VERSION 5.8 ;
BUSBITCHARS "[]" ;
DIVIDERCHAR "/" ;
UNITS
    DATABASE MICRONS 1000 ;
END UNITS

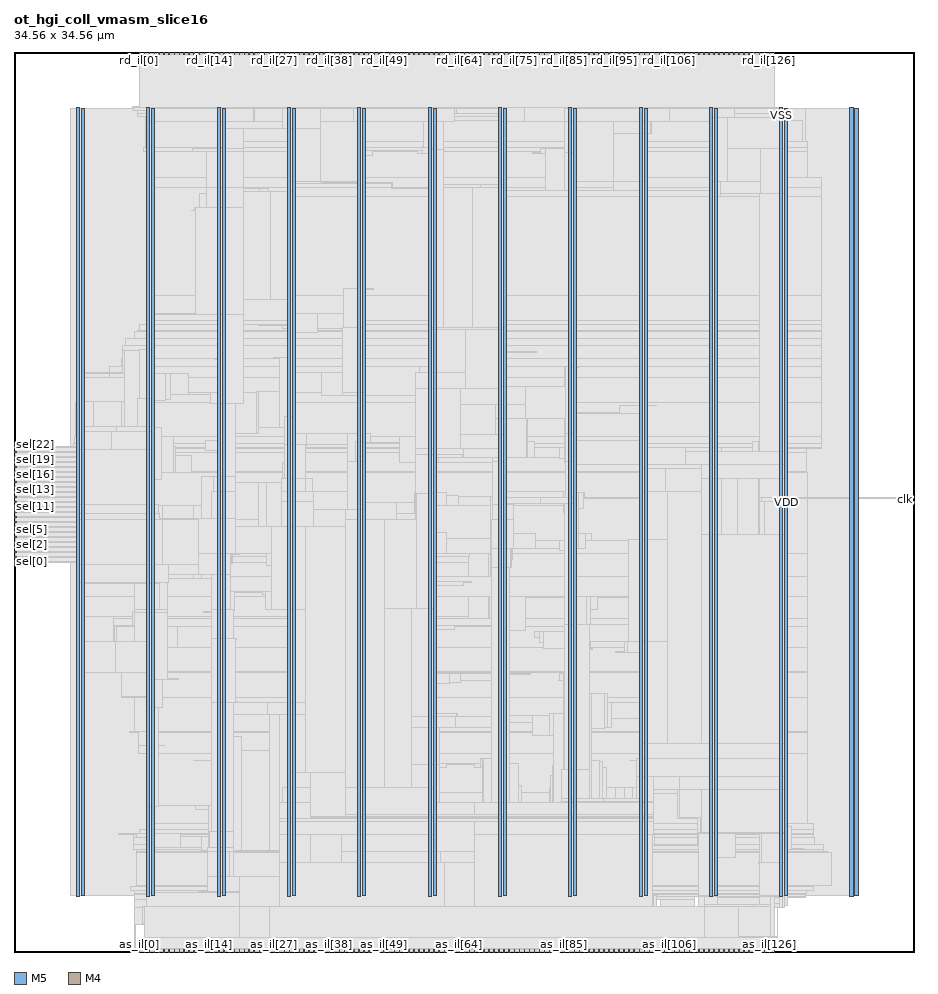
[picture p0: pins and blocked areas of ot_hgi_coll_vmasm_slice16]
MACRO ot_hgi_coll_vmasm_slice16
  FOREIGN ot_hgi_coll_vmasm_slice16 0 0 ;
  CLASS BLOCK ;
  SIZE 34.56 BY 34.56 ;
  PIN as_il[0]
    DIRECTION OUTPUT ;
    USE SIGNAL ;
    PORT
      LAYER M5 ;
        RECT  4.8 0 4.824 0.084 ;
    END
  END as_il[0]
  PIN as_il[100]
    DIRECTION OUTPUT ;
    USE SIGNAL ;
    PORT
      LAYER M5 ;
        RECT  24 0 24.024 0.084 ;
    END
  END as_il[100]
  PIN as_il[101]
    DIRECTION OUTPUT ;
    USE SIGNAL ;
    PORT
      LAYER M5 ;
        RECT  24.192 0 24.216 0.084 ;
    END
  END as_il[101]
  PIN as_il[102]
    DIRECTION OUTPUT ;
    USE SIGNAL ;
    PORT
      LAYER M5 ;
        RECT  24.384 0 24.408 0.084 ;
    END
  END as_il[102]
  PIN as_il[103]
    DIRECTION OUTPUT ;
    USE SIGNAL ;
    PORT
      LAYER M5 ;
        RECT  24.576 0 24.6 0.084 ;
    END
  END as_il[103]
  PIN as_il[104]
    DIRECTION OUTPUT ;
    USE SIGNAL ;
    PORT
      LAYER M5 ;
        RECT  24.768 0 24.792 0.084 ;
    END
  END as_il[104]
  PIN as_il[105]
    DIRECTION OUTPUT ;
    USE SIGNAL ;
    PORT
      LAYER M5 ;
        RECT  24.96 0 24.984 0.084 ;
    END
  END as_il[105]
  PIN as_il[106]
    DIRECTION OUTPUT ;
    USE SIGNAL ;
    PORT
      LAYER M5 ;
        RECT  25.152 0 25.176 0.084 ;
    END
  END as_il[106]
  PIN as_il[107]
    DIRECTION OUTPUT ;
    USE SIGNAL ;
    PORT
      LAYER M5 ;
        RECT  25.344 0 25.368 0.084 ;
    END
  END as_il[107]
  PIN as_il[108]
    DIRECTION OUTPUT ;
    USE SIGNAL ;
    PORT
      LAYER M5 ;
        RECT  25.536 0 25.56 0.084 ;
    END
  END as_il[108]
  PIN as_il[109]
    DIRECTION OUTPUT ;
    USE SIGNAL ;
    PORT
      LAYER M5 ;
        RECT  25.728 0 25.752 0.084 ;
    END
  END as_il[109]
  PIN as_il[10]
    DIRECTION OUTPUT ;
    USE SIGNAL ;
    PORT
      LAYER M5 ;
        RECT  6.72 0 6.744 0.084 ;
    END
  END as_il[10]
  PIN as_il[110]
    DIRECTION OUTPUT ;
    USE SIGNAL ;
    PORT
      LAYER M5 ;
        RECT  25.92 0 25.944 0.084 ;
    END
  END as_il[110]
  PIN as_il[111]
    DIRECTION OUTPUT ;
    USE SIGNAL ;
    PORT
      LAYER M5 ;
        RECT  26.112 0 26.136 0.084 ;
    END
  END as_il[111]
  PIN as_il[112]
    DIRECTION OUTPUT ;
    USE SIGNAL ;
    PORT
      LAYER M5 ;
        RECT  26.304 0 26.328 0.084 ;
    END
  END as_il[112]
  PIN as_il[113]
    DIRECTION OUTPUT ;
    USE SIGNAL ;
    PORT
      LAYER M5 ;
        RECT  26.496 0 26.52 0.084 ;
    END
  END as_il[113]
  PIN as_il[114]
    DIRECTION OUTPUT ;
    USE SIGNAL ;
    PORT
      LAYER M5 ;
        RECT  26.688 0 26.712 0.084 ;
    END
  END as_il[114]
  PIN as_il[115]
    DIRECTION OUTPUT ;
    USE SIGNAL ;
    PORT
      LAYER M5 ;
        RECT  26.88 0 26.904 0.084 ;
    END
  END as_il[115]
  PIN as_il[116]
    DIRECTION OUTPUT ;
    USE SIGNAL ;
    PORT
      LAYER M5 ;
        RECT  27.072 0 27.096 0.084 ;
    END
  END as_il[116]
  PIN as_il[117]
    DIRECTION OUTPUT ;
    USE SIGNAL ;
    PORT
      LAYER M5 ;
        RECT  27.264 0 27.288 0.084 ;
    END
  END as_il[117]
  PIN as_il[118]
    DIRECTION OUTPUT ;
    USE SIGNAL ;
    PORT
      LAYER M5 ;
        RECT  27.456 0 27.48 0.084 ;
    END
  END as_il[118]
  PIN as_il[119]
    DIRECTION OUTPUT ;
    USE SIGNAL ;
    PORT
      LAYER M5 ;
        RECT  27.648 0 27.672 0.084 ;
    END
  END as_il[119]
  PIN as_il[11]
    DIRECTION OUTPUT ;
    USE SIGNAL ;
    PORT
      LAYER M5 ;
        RECT  6.912 0 6.936 0.084 ;
    END
  END as_il[11]
  PIN as_il[120]
    DIRECTION OUTPUT ;
    USE SIGNAL ;
    PORT
      LAYER M5 ;
        RECT  27.84 0 27.864 0.084 ;
    END
  END as_il[120]
  PIN as_il[121]
    DIRECTION OUTPUT ;
    USE SIGNAL ;
    PORT
      LAYER M5 ;
        RECT  28.032 0 28.056 0.084 ;
    END
  END as_il[121]
  PIN as_il[122]
    DIRECTION OUTPUT ;
    USE SIGNAL ;
    PORT
      LAYER M5 ;
        RECT  28.224 0 28.248 0.084 ;
    END
  END as_il[122]
  PIN as_il[123]
    DIRECTION OUTPUT ;
    USE SIGNAL ;
    PORT
      LAYER M5 ;
        RECT  28.416 0 28.44 0.084 ;
    END
  END as_il[123]
  PIN as_il[124]
    DIRECTION OUTPUT ;
    USE SIGNAL ;
    PORT
      LAYER M5 ;
        RECT  28.608 0 28.632 0.084 ;
    END
  END as_il[124]
  PIN as_il[125]
    DIRECTION OUTPUT ;
    USE SIGNAL ;
    PORT
      LAYER M5 ;
        RECT  28.8 0 28.824 0.084 ;
    END
  END as_il[125]
  PIN as_il[126]
    DIRECTION OUTPUT ;
    USE SIGNAL ;
    PORT
      LAYER M5 ;
        RECT  28.992 0 29.016 0.084 ;
    END
  END as_il[126]
  PIN as_il[127]
    DIRECTION OUTPUT ;
    USE SIGNAL ;
    PORT
      LAYER M5 ;
        RECT  29.184 0 29.208 0.084 ;
    END
  END as_il[127]
  PIN as_il[12]
    DIRECTION OUTPUT ;
    USE SIGNAL ;
    PORT
      LAYER M5 ;
        RECT  7.104 0 7.128 0.084 ;
    END
  END as_il[12]
  PIN as_il[13]
    DIRECTION OUTPUT ;
    USE SIGNAL ;
    PORT
      LAYER M5 ;
        RECT  7.296 0 7.32 0.084 ;
    END
  END as_il[13]
  PIN as_il[14]
    DIRECTION OUTPUT ;
    USE SIGNAL ;
    PORT
      LAYER M5 ;
        RECT  7.488 0 7.512 0.084 ;
    END
  END as_il[14]
  PIN as_il[15]
    DIRECTION OUTPUT ;
    USE SIGNAL ;
    PORT
      LAYER M5 ;
        RECT  7.68 0 7.704 0.084 ;
    END
  END as_il[15]
  PIN as_il[16]
    DIRECTION OUTPUT ;
    USE SIGNAL ;
    PORT
      LAYER M5 ;
        RECT  7.872 0 7.896 0.084 ;
    END
  END as_il[16]
  PIN as_il[17]
    DIRECTION OUTPUT ;
    USE SIGNAL ;
    PORT
      LAYER M5 ;
        RECT  8.064 0 8.088 0.084 ;
    END
  END as_il[17]
  PIN as_il[18]
    DIRECTION OUTPUT ;
    USE SIGNAL ;
    PORT
      LAYER M5 ;
        RECT  8.256 0 8.28 0.084 ;
    END
  END as_il[18]
  PIN as_il[19]
    DIRECTION OUTPUT ;
    USE SIGNAL ;
    PORT
      LAYER M5 ;
        RECT  8.448 0 8.472 0.084 ;
    END
  END as_il[19]
  PIN as_il[1]
    DIRECTION OUTPUT ;
    USE SIGNAL ;
    PORT
      LAYER M5 ;
        RECT  4.992 0 5.016 0.084 ;
    END
  END as_il[1]
  PIN as_il[20]
    DIRECTION OUTPUT ;
    USE SIGNAL ;
    PORT
      LAYER M5 ;
        RECT  8.64 0 8.664 0.084 ;
    END
  END as_il[20]
  PIN as_il[21]
    DIRECTION OUTPUT ;
    USE SIGNAL ;
    PORT
      LAYER M5 ;
        RECT  8.832 0 8.856 0.084 ;
    END
  END as_il[21]
  PIN as_il[22]
    DIRECTION OUTPUT ;
    USE SIGNAL ;
    PORT
      LAYER M5 ;
        RECT  9.024 0 9.048 0.084 ;
    END
  END as_il[22]
  PIN as_il[23]
    DIRECTION OUTPUT ;
    USE SIGNAL ;
    PORT
      LAYER M5 ;
        RECT  9.216 0 9.24 0.084 ;
    END
  END as_il[23]
  PIN as_il[24]
    DIRECTION OUTPUT ;
    USE SIGNAL ;
    PORT
      LAYER M5 ;
        RECT  9.408 0 9.432 0.084 ;
    END
  END as_il[24]
  PIN as_il[25]
    DIRECTION OUTPUT ;
    USE SIGNAL ;
    PORT
      LAYER M5 ;
        RECT  9.6 0 9.624 0.084 ;
    END
  END as_il[25]
  PIN as_il[26]
    DIRECTION OUTPUT ;
    USE SIGNAL ;
    PORT
      LAYER M5 ;
        RECT  9.792 0 9.816 0.084 ;
    END
  END as_il[26]
  PIN as_il[27]
    DIRECTION OUTPUT ;
    USE SIGNAL ;
    PORT
      LAYER M5 ;
        RECT  9.984 0 10.008 0.084 ;
    END
  END as_il[27]
  PIN as_il[28]
    DIRECTION OUTPUT ;
    USE SIGNAL ;
    PORT
      LAYER M5 ;
        RECT  10.176 0 10.2 0.084 ;
    END
  END as_il[28]
  PIN as_il[29]
    DIRECTION OUTPUT ;
    USE SIGNAL ;
    PORT
      LAYER M5 ;
        RECT  10.368 0 10.392 0.084 ;
    END
  END as_il[29]
  PIN as_il[2]
    DIRECTION OUTPUT ;
    USE SIGNAL ;
    PORT
      LAYER M5 ;
        RECT  5.184 0 5.208 0.084 ;
    END
  END as_il[2]
  PIN as_il[30]
    DIRECTION OUTPUT ;
    USE SIGNAL ;
    PORT
      LAYER M5 ;
        RECT  10.56 0 10.584 0.084 ;
    END
  END as_il[30]
  PIN as_il[31]
    DIRECTION OUTPUT ;
    USE SIGNAL ;
    PORT
      LAYER M5 ;
        RECT  10.752 0 10.776 0.084 ;
    END
  END as_il[31]
  PIN as_il[32]
    DIRECTION OUTPUT ;
    USE SIGNAL ;
    PORT
      LAYER M5 ;
        RECT  10.944 0 10.968 0.084 ;
    END
  END as_il[32]
  PIN as_il[33]
    DIRECTION OUTPUT ;
    USE SIGNAL ;
    PORT
      LAYER M5 ;
        RECT  11.136 0 11.16 0.084 ;
    END
  END as_il[33]
  PIN as_il[34]
    DIRECTION OUTPUT ;
    USE SIGNAL ;
    PORT
      LAYER M5 ;
        RECT  11.328 0 11.352 0.084 ;
    END
  END as_il[34]
  PIN as_il[35]
    DIRECTION OUTPUT ;
    USE SIGNAL ;
    PORT
      LAYER M5 ;
        RECT  11.52 0 11.544 0.084 ;
    END
  END as_il[35]
  PIN as_il[36]
    DIRECTION OUTPUT ;
    USE SIGNAL ;
    PORT
      LAYER M5 ;
        RECT  11.712 0 11.736 0.084 ;
    END
  END as_il[36]
  PIN as_il[37]
    DIRECTION OUTPUT ;
    USE SIGNAL ;
    PORT
      LAYER M5 ;
        RECT  11.904 0 11.928 0.084 ;
    END
  END as_il[37]
  PIN as_il[38]
    DIRECTION OUTPUT ;
    USE SIGNAL ;
    PORT
      LAYER M5 ;
        RECT  12.096 0 12.12 0.084 ;
    END
  END as_il[38]
  PIN as_il[39]
    DIRECTION OUTPUT ;
    USE SIGNAL ;
    PORT
      LAYER M5 ;
        RECT  12.288 0 12.312 0.084 ;
    END
  END as_il[39]
  PIN as_il[3]
    DIRECTION OUTPUT ;
    USE SIGNAL ;
    PORT
      LAYER M5 ;
        RECT  5.376 0 5.4 0.084 ;
    END
  END as_il[3]
  PIN as_il[40]
    DIRECTION OUTPUT ;
    USE SIGNAL ;
    PORT
      LAYER M5 ;
        RECT  12.48 0 12.504 0.084 ;
    END
  END as_il[40]
  PIN as_il[41]
    DIRECTION OUTPUT ;
    USE SIGNAL ;
    PORT
      LAYER M5 ;
        RECT  12.672 0 12.696 0.084 ;
    END
  END as_il[41]
  PIN as_il[42]
    DIRECTION OUTPUT ;
    USE SIGNAL ;
    PORT
      LAYER M5 ;
        RECT  12.864 0 12.888 0.084 ;
    END
  END as_il[42]
  PIN as_il[43]
    DIRECTION OUTPUT ;
    USE SIGNAL ;
    PORT
      LAYER M5 ;
        RECT  13.056 0 13.08 0.084 ;
    END
  END as_il[43]
  PIN as_il[44]
    DIRECTION OUTPUT ;
    USE SIGNAL ;
    PORT
      LAYER M5 ;
        RECT  13.248 0 13.272 0.084 ;
    END
  END as_il[44]
  PIN as_il[45]
    DIRECTION OUTPUT ;
    USE SIGNAL ;
    PORT
      LAYER M5 ;
        RECT  13.44 0 13.464 0.084 ;
    END
  END as_il[45]
  PIN as_il[46]
    DIRECTION OUTPUT ;
    USE SIGNAL ;
    PORT
      LAYER M5 ;
        RECT  13.632 0 13.656 0.084 ;
    END
  END as_il[46]
  PIN as_il[47]
    DIRECTION OUTPUT ;
    USE SIGNAL ;
    PORT
      LAYER M5 ;
        RECT  13.824 0 13.848 0.084 ;
    END
  END as_il[47]
  PIN as_il[48]
    DIRECTION OUTPUT ;
    USE SIGNAL ;
    PORT
      LAYER M5 ;
        RECT  14.016 0 14.04 0.084 ;
    END
  END as_il[48]
  PIN as_il[49]
    DIRECTION OUTPUT ;
    USE SIGNAL ;
    PORT
      LAYER M5 ;
        RECT  14.208 0 14.232 0.084 ;
    END
  END as_il[49]
  PIN as_il[4]
    DIRECTION OUTPUT ;
    USE SIGNAL ;
    PORT
      LAYER M5 ;
        RECT  5.568 0 5.592 0.084 ;
    END
  END as_il[4]
  PIN as_il[50]
    DIRECTION OUTPUT ;
    USE SIGNAL ;
    PORT
      LAYER M5 ;
        RECT  14.4 0 14.424 0.084 ;
    END
  END as_il[50]
  PIN as_il[51]
    DIRECTION OUTPUT ;
    USE SIGNAL ;
    PORT
      LAYER M5 ;
        RECT  14.592 0 14.616 0.084 ;
    END
  END as_il[51]
  PIN as_il[52]
    DIRECTION OUTPUT ;
    USE SIGNAL ;
    PORT
      LAYER M5 ;
        RECT  14.784 0 14.808 0.084 ;
    END
  END as_il[52]
  PIN as_il[53]
    DIRECTION OUTPUT ;
    USE SIGNAL ;
    PORT
      LAYER M5 ;
        RECT  14.976 0 15 0.084 ;
    END
  END as_il[53]
  PIN as_il[54]
    DIRECTION OUTPUT ;
    USE SIGNAL ;
    PORT
      LAYER M5 ;
        RECT  15.168 0 15.192 0.084 ;
    END
  END as_il[54]
  PIN as_il[55]
    DIRECTION OUTPUT ;
    USE SIGNAL ;
    PORT
      LAYER M5 ;
        RECT  15.36 0 15.384 0.084 ;
    END
  END as_il[55]
  PIN as_il[56]
    DIRECTION OUTPUT ;
    USE SIGNAL ;
    PORT
      LAYER M5 ;
        RECT  15.552 0 15.576 0.084 ;
    END
  END as_il[56]
  PIN as_il[57]
    DIRECTION OUTPUT ;
    USE SIGNAL ;
    PORT
      LAYER M5 ;
        RECT  15.744 0 15.768 0.084 ;
    END
  END as_il[57]
  PIN as_il[58]
    DIRECTION OUTPUT ;
    USE SIGNAL ;
    PORT
      LAYER M5 ;
        RECT  15.936 0 15.96 0.084 ;
    END
  END as_il[58]
  PIN as_il[59]
    DIRECTION OUTPUT ;
    USE SIGNAL ;
    PORT
      LAYER M5 ;
        RECT  16.128 0 16.152 0.084 ;
    END
  END as_il[59]
  PIN as_il[5]
    DIRECTION OUTPUT ;
    USE SIGNAL ;
    PORT
      LAYER M5 ;
        RECT  5.76 0 5.784 0.084 ;
    END
  END as_il[5]
  PIN as_il[60]
    DIRECTION OUTPUT ;
    USE SIGNAL ;
    PORT
      LAYER M5 ;
        RECT  16.32 0 16.344 0.084 ;
    END
  END as_il[60]
  PIN as_il[61]
    DIRECTION OUTPUT ;
    USE SIGNAL ;
    PORT
      LAYER M5 ;
        RECT  16.512 0 16.536 0.084 ;
    END
  END as_il[61]
  PIN as_il[62]
    DIRECTION OUTPUT ;
    USE SIGNAL ;
    PORT
      LAYER M5 ;
        RECT  16.704 0 16.728 0.084 ;
    END
  END as_il[62]
  PIN as_il[63]
    DIRECTION OUTPUT ;
    USE SIGNAL ;
    PORT
      LAYER M5 ;
        RECT  16.896 0 16.92 0.084 ;
    END
  END as_il[63]
  PIN as_il[64]
    DIRECTION OUTPUT ;
    USE SIGNAL ;
    PORT
      LAYER M5 ;
        RECT  17.088 0 17.112 0.084 ;
    END
  END as_il[64]
  PIN as_il[65]
    DIRECTION OUTPUT ;
    USE SIGNAL ;
    PORT
      LAYER M5 ;
        RECT  17.28 0 17.304 0.084 ;
    END
  END as_il[65]
  PIN as_il[66]
    DIRECTION OUTPUT ;
    USE SIGNAL ;
    PORT
      LAYER M5 ;
        RECT  17.472 0 17.496 0.084 ;
    END
  END as_il[66]
  PIN as_il[67]
    DIRECTION OUTPUT ;
    USE SIGNAL ;
    PORT
      LAYER M5 ;
        RECT  17.664 0 17.688 0.084 ;
    END
  END as_il[67]
  PIN as_il[68]
    DIRECTION OUTPUT ;
    USE SIGNAL ;
    PORT
      LAYER M5 ;
        RECT  17.856 0 17.88 0.084 ;
    END
  END as_il[68]
  PIN as_il[69]
    DIRECTION OUTPUT ;
    USE SIGNAL ;
    PORT
      LAYER M5 ;
        RECT  18.048 0 18.072 0.084 ;
    END
  END as_il[69]
  PIN as_il[6]
    DIRECTION OUTPUT ;
    USE SIGNAL ;
    PORT
      LAYER M5 ;
        RECT  5.952 0 5.976 0.084 ;
    END
  END as_il[6]
  PIN as_il[70]
    DIRECTION OUTPUT ;
    USE SIGNAL ;
    PORT
      LAYER M5 ;
        RECT  18.24 0 18.264 0.084 ;
    END
  END as_il[70]
  PIN as_il[71]
    DIRECTION OUTPUT ;
    USE SIGNAL ;
    PORT
      LAYER M5 ;
        RECT  18.432 0 18.456 0.084 ;
    END
  END as_il[71]
  PIN as_il[72]
    DIRECTION OUTPUT ;
    USE SIGNAL ;
    PORT
      LAYER M5 ;
        RECT  18.624 0 18.648 0.084 ;
    END
  END as_il[72]
  PIN as_il[73]
    DIRECTION OUTPUT ;
    USE SIGNAL ;
    PORT
      LAYER M5 ;
        RECT  18.816 0 18.84 0.084 ;
    END
  END as_il[73]
  PIN as_il[74]
    DIRECTION OUTPUT ;
    USE SIGNAL ;
    PORT
      LAYER M5 ;
        RECT  19.008 0 19.032 0.084 ;
    END
  END as_il[74]
  PIN as_il[75]
    DIRECTION OUTPUT ;
    USE SIGNAL ;
    PORT
      LAYER M5 ;
        RECT  19.2 0 19.224 0.084 ;
    END
  END as_il[75]
  PIN as_il[76]
    DIRECTION OUTPUT ;
    USE SIGNAL ;
    PORT
      LAYER M5 ;
        RECT  19.392 0 19.416 0.084 ;
    END
  END as_il[76]
  PIN as_il[77]
    DIRECTION OUTPUT ;
    USE SIGNAL ;
    PORT
      LAYER M5 ;
        RECT  19.584 0 19.608 0.084 ;
    END
  END as_il[77]
  PIN as_il[78]
    DIRECTION OUTPUT ;
    USE SIGNAL ;
    PORT
      LAYER M5 ;
        RECT  19.776 0 19.8 0.084 ;
    END
  END as_il[78]
  PIN as_il[79]
    DIRECTION OUTPUT ;
    USE SIGNAL ;
    PORT
      LAYER M5 ;
        RECT  19.968 0 19.992 0.084 ;
    END
  END as_il[79]
  PIN as_il[7]
    DIRECTION OUTPUT ;
    USE SIGNAL ;
    PORT
      LAYER M5 ;
        RECT  6.144 0 6.168 0.084 ;
    END
  END as_il[7]
  PIN as_il[80]
    DIRECTION OUTPUT ;
    USE SIGNAL ;
    PORT
      LAYER M5 ;
        RECT  20.16 0 20.184 0.084 ;
    END
  END as_il[80]
  PIN as_il[81]
    DIRECTION OUTPUT ;
    USE SIGNAL ;
    PORT
      LAYER M5 ;
        RECT  20.352 0 20.376 0.084 ;
    END
  END as_il[81]
  PIN as_il[82]
    DIRECTION OUTPUT ;
    USE SIGNAL ;
    PORT
      LAYER M5 ;
        RECT  20.544 0 20.568 0.084 ;
    END
  END as_il[82]
  PIN as_il[83]
    DIRECTION OUTPUT ;
    USE SIGNAL ;
    PORT
      LAYER M5 ;
        RECT  20.736 0 20.76 0.084 ;
    END
  END as_il[83]
  PIN as_il[84]
    DIRECTION OUTPUT ;
    USE SIGNAL ;
    PORT
      LAYER M5 ;
        RECT  20.928 0 20.952 0.084 ;
    END
  END as_il[84]
  PIN as_il[85]
    DIRECTION OUTPUT ;
    USE SIGNAL ;
    PORT
      LAYER M5 ;
        RECT  21.12 0 21.144 0.084 ;
    END
  END as_il[85]
  PIN as_il[86]
    DIRECTION OUTPUT ;
    USE SIGNAL ;
    PORT
      LAYER M5 ;
        RECT  21.312 0 21.336 0.084 ;
    END
  END as_il[86]
  PIN as_il[87]
    DIRECTION OUTPUT ;
    USE SIGNAL ;
    PORT
      LAYER M5 ;
        RECT  21.504 0 21.528 0.084 ;
    END
  END as_il[87]
  PIN as_il[88]
    DIRECTION OUTPUT ;
    USE SIGNAL ;
    PORT
      LAYER M5 ;
        RECT  21.696 0 21.72 0.084 ;
    END
  END as_il[88]
  PIN as_il[89]
    DIRECTION OUTPUT ;
    USE SIGNAL ;
    PORT
      LAYER M5 ;
        RECT  21.888 0 21.912 0.084 ;
    END
  END as_il[89]
  PIN as_il[8]
    DIRECTION OUTPUT ;
    USE SIGNAL ;
    PORT
      LAYER M5 ;
        RECT  6.336 0 6.36 0.084 ;
    END
  END as_il[8]
  PIN as_il[90]
    DIRECTION OUTPUT ;
    USE SIGNAL ;
    PORT
      LAYER M5 ;
        RECT  22.08 0 22.104 0.084 ;
    END
  END as_il[90]
  PIN as_il[91]
    DIRECTION OUTPUT ;
    USE SIGNAL ;
    PORT
      LAYER M5 ;
        RECT  22.272 0 22.296 0.084 ;
    END
  END as_il[91]
  PIN as_il[92]
    DIRECTION OUTPUT ;
    USE SIGNAL ;
    PORT
      LAYER M5 ;
        RECT  22.464 0 22.488 0.084 ;
    END
  END as_il[92]
  PIN as_il[93]
    DIRECTION OUTPUT ;
    USE SIGNAL ;
    PORT
      LAYER M5 ;
        RECT  22.656 0 22.68 0.084 ;
    END
  END as_il[93]
  PIN as_il[94]
    DIRECTION OUTPUT ;
    USE SIGNAL ;
    PORT
      LAYER M5 ;
        RECT  22.848 0 22.872 0.084 ;
    END
  END as_il[94]
  PIN as_il[95]
    DIRECTION OUTPUT ;
    USE SIGNAL ;
    PORT
      LAYER M5 ;
        RECT  23.04 0 23.064 0.084 ;
    END
  END as_il[95]
  PIN as_il[96]
    DIRECTION OUTPUT ;
    USE SIGNAL ;
    PORT
      LAYER M5 ;
        RECT  23.232 0 23.256 0.084 ;
    END
  END as_il[96]
  PIN as_il[97]
    DIRECTION OUTPUT ;
    USE SIGNAL ;
    PORT
      LAYER M5 ;
        RECT  23.424 0 23.448 0.084 ;
    END
  END as_il[97]
  PIN as_il[98]
    DIRECTION OUTPUT ;
    USE SIGNAL ;
    PORT
      LAYER M5 ;
        RECT  23.616 0 23.64 0.084 ;
    END
  END as_il[98]
  PIN as_il[99]
    DIRECTION OUTPUT ;
    USE SIGNAL ;
    PORT
      LAYER M5 ;
        RECT  23.808 0 23.832 0.084 ;
    END
  END as_il[99]
  PIN as_il[9]
    DIRECTION OUTPUT ;
    USE SIGNAL ;
    PORT
      LAYER M5 ;
        RECT  6.528 0 6.552 0.084 ;
    END
  END as_il[9]
  PIN clk
    DIRECTION INPUT ;
    USE SIGNAL ;
    PORT
      LAYER M4 ;
        RECT  34.476 17.28 34.56 17.304 ;
    END
    PORT
      LAYER M4 ;
        RECT  34.441 17.28 34.481 17.448 ;
    END
    PORT
      LAYER M4 ;
        RECT  34.481 17.28 34.524 17.304 ;
    END
  END clk
  PIN rd_il[0]
    DIRECTION INPUT ;
    USE SIGNAL ;
    PORT
      LAYER M5 ;
        RECT  4.8 34.476 4.824 34.56 ;
    END
  END rd_il[0]
  PIN rd_il[100]
    DIRECTION INPUT ;
    USE SIGNAL ;
    PORT
      LAYER M5 ;
        RECT  24 34.476 24.024 34.56 ;
    END
  END rd_il[100]
  PIN rd_il[101]
    DIRECTION INPUT ;
    USE SIGNAL ;
    PORT
      LAYER M5 ;
        RECT  24.192 34.476 24.216 34.56 ;
    END
  END rd_il[101]
  PIN rd_il[102]
    DIRECTION INPUT ;
    USE SIGNAL ;
    PORT
      LAYER M5 ;
        RECT  24.384 34.476 24.408 34.56 ;
    END
  END rd_il[102]
  PIN rd_il[103]
    DIRECTION INPUT ;
    USE SIGNAL ;
    PORT
      LAYER M5 ;
        RECT  24.576 34.476 24.6 34.56 ;
    END
  END rd_il[103]
  PIN rd_il[104]
    DIRECTION INPUT ;
    USE SIGNAL ;
    PORT
      LAYER M5 ;
        RECT  24.768 34.476 24.792 34.56 ;
    END
  END rd_il[104]
  PIN rd_il[105]
    DIRECTION INPUT ;
    USE SIGNAL ;
    PORT
      LAYER M5 ;
        RECT  24.96 34.476 24.984 34.56 ;
    END
  END rd_il[105]
  PIN rd_il[106]
    DIRECTION INPUT ;
    USE SIGNAL ;
    PORT
      LAYER M5 ;
        RECT  25.152 34.476 25.176 34.56 ;
    END
  END rd_il[106]
  PIN rd_il[107]
    DIRECTION INPUT ;
    USE SIGNAL ;
    PORT
      LAYER M5 ;
        RECT  25.344 34.476 25.368 34.56 ;
    END
  END rd_il[107]
  PIN rd_il[108]
    DIRECTION INPUT ;
    USE SIGNAL ;
    PORT
      LAYER M5 ;
        RECT  25.536 34.476 25.56 34.56 ;
    END
  END rd_il[108]
  PIN rd_il[109]
    DIRECTION INPUT ;
    USE SIGNAL ;
    PORT
      LAYER M5 ;
        RECT  25.728 34.476 25.752 34.56 ;
    END
  END rd_il[109]
  PIN rd_il[10]
    DIRECTION INPUT ;
    USE SIGNAL ;
    PORT
      LAYER M5 ;
        RECT  6.72 34.476 6.744 34.56 ;
    END
  END rd_il[10]
  PIN rd_il[110]
    DIRECTION INPUT ;
    USE SIGNAL ;
    PORT
      LAYER M5 ;
        RECT  25.92 34.476 25.944 34.56 ;
    END
  END rd_il[110]
  PIN rd_il[111]
    DIRECTION INPUT ;
    USE SIGNAL ;
    PORT
      LAYER M5 ;
        RECT  26.112 34.476 26.136 34.56 ;
    END
  END rd_il[111]
  PIN rd_il[112]
    DIRECTION INPUT ;
    USE SIGNAL ;
    PORT
      LAYER M5 ;
        RECT  26.304 34.476 26.328 34.56 ;
    END
  END rd_il[112]
  PIN rd_il[113]
    DIRECTION INPUT ;
    USE SIGNAL ;
    PORT
      LAYER M5 ;
        RECT  26.496 34.476 26.52 34.56 ;
    END
  END rd_il[113]
  PIN rd_il[114]
    DIRECTION INPUT ;
    USE SIGNAL ;
    PORT
      LAYER M5 ;
        RECT  26.688 34.476 26.712 34.56 ;
    END
  END rd_il[114]
  PIN rd_il[115]
    DIRECTION INPUT ;
    USE SIGNAL ;
    PORT
      LAYER M5 ;
        RECT  26.88 34.476 26.904 34.56 ;
    END
  END rd_il[115]
  PIN rd_il[116]
    DIRECTION INPUT ;
    USE SIGNAL ;
    PORT
      LAYER M5 ;
        RECT  27.072 34.476 27.096 34.56 ;
    END
  END rd_il[116]
  PIN rd_il[117]
    DIRECTION INPUT ;
    USE SIGNAL ;
    PORT
      LAYER M5 ;
        RECT  27.264 34.476 27.288 34.56 ;
    END
  END rd_il[117]
  PIN rd_il[118]
    DIRECTION INPUT ;
    USE SIGNAL ;
    PORT
      LAYER M5 ;
        RECT  27.456 34.476 27.48 34.56 ;
    END
  END rd_il[118]
  PIN rd_il[119]
    DIRECTION INPUT ;
    USE SIGNAL ;
    PORT
      LAYER M5 ;
        RECT  27.648 34.476 27.672 34.56 ;
    END
  END rd_il[119]
  PIN rd_il[11]
    DIRECTION INPUT ;
    USE SIGNAL ;
    PORT
      LAYER M5 ;
        RECT  6.912 34.476 6.936 34.56 ;
    END
  END rd_il[11]
  PIN rd_il[120]
    DIRECTION INPUT ;
    USE SIGNAL ;
    PORT
      LAYER M5 ;
        RECT  27.84 34.476 27.864 34.56 ;
    END
  END rd_il[120]
  PIN rd_il[121]
    DIRECTION INPUT ;
    USE SIGNAL ;
    PORT
      LAYER M5 ;
        RECT  28.032 34.476 28.056 34.56 ;
    END
  END rd_il[121]
  PIN rd_il[122]
    DIRECTION INPUT ;
    USE SIGNAL ;
    PORT
      LAYER M5 ;
        RECT  28.224 34.476 28.248 34.56 ;
    END
  END rd_il[122]
  PIN rd_il[123]
    DIRECTION INPUT ;
    USE SIGNAL ;
    PORT
      LAYER M5 ;
        RECT  28.416 34.476 28.44 34.56 ;
    END
  END rd_il[123]
  PIN rd_il[124]
    DIRECTION INPUT ;
    USE SIGNAL ;
    PORT
      LAYER M5 ;
        RECT  28.608 34.476 28.632 34.56 ;
    END
  END rd_il[124]
  PIN rd_il[125]
    DIRECTION INPUT ;
    USE SIGNAL ;
    PORT
      LAYER M5 ;
        RECT  28.8 34.476 28.824 34.56 ;
    END
  END rd_il[125]
  PIN rd_il[126]
    DIRECTION INPUT ;
    USE SIGNAL ;
    PORT
      LAYER M5 ;
        RECT  28.992 34.476 29.016 34.56 ;
    END
  END rd_il[126]
  PIN rd_il[127]
    DIRECTION INPUT ;
    USE SIGNAL ;
    PORT
      LAYER M5 ;
        RECT  29.184 34.476 29.208 34.56 ;
    END
  END rd_il[127]
  PIN rd_il[12]
    DIRECTION INPUT ;
    USE SIGNAL ;
    PORT
      LAYER M5 ;
        RECT  7.104 34.476 7.128 34.56 ;
    END
  END rd_il[12]
  PIN rd_il[13]
    DIRECTION INPUT ;
    USE SIGNAL ;
    PORT
      LAYER M5 ;
        RECT  7.296 34.476 7.32 34.56 ;
    END
  END rd_il[13]
  PIN rd_il[14]
    DIRECTION INPUT ;
    USE SIGNAL ;
    PORT
      LAYER M5 ;
        RECT  7.488 34.476 7.512 34.56 ;
    END
  END rd_il[14]
  PIN rd_il[15]
    DIRECTION INPUT ;
    USE SIGNAL ;
    PORT
      LAYER M5 ;
        RECT  7.68 34.476 7.704 34.56 ;
    END
  END rd_il[15]
  PIN rd_il[16]
    DIRECTION INPUT ;
    USE SIGNAL ;
    PORT
      LAYER M5 ;
        RECT  7.872 34.476 7.896 34.56 ;
    END
  END rd_il[16]
  PIN rd_il[17]
    DIRECTION INPUT ;
    USE SIGNAL ;
    PORT
      LAYER M5 ;
        RECT  8.064 34.476 8.088 34.56 ;
    END
  END rd_il[17]
  PIN rd_il[18]
    DIRECTION INPUT ;
    USE SIGNAL ;
    PORT
      LAYER M5 ;
        RECT  8.256 34.476 8.28 34.56 ;
    END
  END rd_il[18]
  PIN rd_il[19]
    DIRECTION INPUT ;
    USE SIGNAL ;
    PORT
      LAYER M5 ;
        RECT  8.448 34.476 8.472 34.56 ;
    END
  END rd_il[19]
  PIN rd_il[1]
    DIRECTION INPUT ;
    USE SIGNAL ;
    PORT
      LAYER M5 ;
        RECT  4.992 34.476 5.016 34.56 ;
    END
  END rd_il[1]
  PIN rd_il[20]
    DIRECTION INPUT ;
    USE SIGNAL ;
    PORT
      LAYER M5 ;
        RECT  8.64 34.476 8.664 34.56 ;
    END
  END rd_il[20]
  PIN rd_il[21]
    DIRECTION INPUT ;
    USE SIGNAL ;
    PORT
      LAYER M5 ;
        RECT  8.832 34.476 8.856 34.56 ;
    END
  END rd_il[21]
  PIN rd_il[22]
    DIRECTION INPUT ;
    USE SIGNAL ;
    PORT
      LAYER M5 ;
        RECT  9.024 34.476 9.048 34.56 ;
    END
  END rd_il[22]
  PIN rd_il[23]
    DIRECTION INPUT ;
    USE SIGNAL ;
    PORT
      LAYER M5 ;
        RECT  9.216 34.476 9.24 34.56 ;
    END
  END rd_il[23]
  PIN rd_il[24]
    DIRECTION INPUT ;
    USE SIGNAL ;
    PORT
      LAYER M5 ;
        RECT  9.408 34.476 9.432 34.56 ;
    END
  END rd_il[24]
  PIN rd_il[25]
    DIRECTION INPUT ;
    USE SIGNAL ;
    PORT
      LAYER M5 ;
        RECT  9.6 34.476 9.624 34.56 ;
    END
  END rd_il[25]
  PIN rd_il[26]
    DIRECTION INPUT ;
    USE SIGNAL ;
    PORT
      LAYER M5 ;
        RECT  9.792 34.476 9.816 34.56 ;
    END
  END rd_il[26]
  PIN rd_il[27]
    DIRECTION INPUT ;
    USE SIGNAL ;
    PORT
      LAYER M5 ;
        RECT  9.984 34.476 10.008 34.56 ;
    END
  END rd_il[27]
  PIN rd_il[28]
    DIRECTION INPUT ;
    USE SIGNAL ;
    PORT
      LAYER M5 ;
        RECT  10.176 34.476 10.2 34.56 ;
    END
  END rd_il[28]
  PIN rd_il[29]
    DIRECTION INPUT ;
    USE SIGNAL ;
    PORT
      LAYER M5 ;
        RECT  10.368 34.476 10.392 34.56 ;
    END
  END rd_il[29]
  PIN rd_il[2]
    DIRECTION INPUT ;
    USE SIGNAL ;
    PORT
      LAYER M5 ;
        RECT  5.184 34.476 5.208 34.56 ;
    END
  END rd_il[2]
  PIN rd_il[30]
    DIRECTION INPUT ;
    USE SIGNAL ;
    PORT
      LAYER M5 ;
        RECT  10.56 34.476 10.584 34.56 ;
    END
  END rd_il[30]
  PIN rd_il[31]
    DIRECTION INPUT ;
    USE SIGNAL ;
    PORT
      LAYER M5 ;
        RECT  10.752 34.476 10.776 34.56 ;
    END
  END rd_il[31]
  PIN rd_il[32]
    DIRECTION INPUT ;
    USE SIGNAL ;
    PORT
      LAYER M5 ;
        RECT  10.944 34.476 10.968 34.56 ;
    END
  END rd_il[32]
  PIN rd_il[33]
    DIRECTION INPUT ;
    USE SIGNAL ;
    PORT
      LAYER M5 ;
        RECT  11.136 34.476 11.16 34.56 ;
    END
  END rd_il[33]
  PIN rd_il[34]
    DIRECTION INPUT ;
    USE SIGNAL ;
    PORT
      LAYER M5 ;
        RECT  11.328 34.476 11.352 34.56 ;
    END
  END rd_il[34]
  PIN rd_il[35]
    DIRECTION INPUT ;
    USE SIGNAL ;
    PORT
      LAYER M5 ;
        RECT  11.52 34.476 11.544 34.56 ;
    END
  END rd_il[35]
  PIN rd_il[36]
    DIRECTION INPUT ;
    USE SIGNAL ;
    PORT
      LAYER M5 ;
        RECT  11.712 34.476 11.736 34.56 ;
    END
  END rd_il[36]
  PIN rd_il[37]
    DIRECTION INPUT ;
    USE SIGNAL ;
    PORT
      LAYER M5 ;
        RECT  11.904 34.476 11.928 34.56 ;
    END
  END rd_il[37]
  PIN rd_il[38]
    DIRECTION INPUT ;
    USE SIGNAL ;
    PORT
      LAYER M5 ;
        RECT  12.096 34.476 12.12 34.56 ;
    END
  END rd_il[38]
  PIN rd_il[39]
    DIRECTION INPUT ;
    USE SIGNAL ;
    PORT
      LAYER M5 ;
        RECT  12.288 34.476 12.312 34.56 ;
    END
  END rd_il[39]
  PIN rd_il[3]
    DIRECTION INPUT ;
    USE SIGNAL ;
    PORT
      LAYER M5 ;
        RECT  5.376 34.476 5.4 34.56 ;
    END
  END rd_il[3]
  PIN rd_il[40]
    DIRECTION INPUT ;
    USE SIGNAL ;
    PORT
      LAYER M5 ;
        RECT  12.48 34.476 12.504 34.56 ;
    END
  END rd_il[40]
  PIN rd_il[41]
    DIRECTION INPUT ;
    USE SIGNAL ;
    PORT
      LAYER M5 ;
        RECT  12.672 34.476 12.696 34.56 ;
    END
  END rd_il[41]
  PIN rd_il[42]
    DIRECTION INPUT ;
    USE SIGNAL ;
    PORT
      LAYER M5 ;
        RECT  12.864 34.476 12.888 34.56 ;
    END
  END rd_il[42]
  PIN rd_il[43]
    DIRECTION INPUT ;
    USE SIGNAL ;
    PORT
      LAYER M5 ;
        RECT  13.056 34.476 13.08 34.56 ;
    END
  END rd_il[43]
  PIN rd_il[44]
    DIRECTION INPUT ;
    USE SIGNAL ;
    PORT
      LAYER M5 ;
        RECT  13.248 34.476 13.272 34.56 ;
    END
  END rd_il[44]
  PIN rd_il[45]
    DIRECTION INPUT ;
    USE SIGNAL ;
    PORT
      LAYER M5 ;
        RECT  13.44 34.476 13.464 34.56 ;
    END
  END rd_il[45]
  PIN rd_il[46]
    DIRECTION INPUT ;
    USE SIGNAL ;
    PORT
      LAYER M5 ;
        RECT  13.632 34.476 13.656 34.56 ;
    END
  END rd_il[46]
  PIN rd_il[47]
    DIRECTION INPUT ;
    USE SIGNAL ;
    PORT
      LAYER M5 ;
        RECT  13.824 34.476 13.848 34.56 ;
    END
  END rd_il[47]
  PIN rd_il[48]
    DIRECTION INPUT ;
    USE SIGNAL ;
    PORT
      LAYER M5 ;
        RECT  14.016 34.476 14.04 34.56 ;
    END
  END rd_il[48]
  PIN rd_il[49]
    DIRECTION INPUT ;
    USE SIGNAL ;
    PORT
      LAYER M5 ;
        RECT  14.208 34.476 14.232 34.56 ;
    END
  END rd_il[49]
  PIN rd_il[4]
    DIRECTION INPUT ;
    USE SIGNAL ;
    PORT
      LAYER M5 ;
        RECT  5.568 34.476 5.592 34.56 ;
    END
  END rd_il[4]
  PIN rd_il[50]
    DIRECTION INPUT ;
    USE SIGNAL ;
    PORT
      LAYER M5 ;
        RECT  14.4 34.476 14.424 34.56 ;
    END
  END rd_il[50]
  PIN rd_il[51]
    DIRECTION INPUT ;
    USE SIGNAL ;
    PORT
      LAYER M5 ;
        RECT  14.592 34.476 14.616 34.56 ;
    END
  END rd_il[51]
  PIN rd_il[52]
    DIRECTION INPUT ;
    USE SIGNAL ;
    PORT
      LAYER M5 ;
        RECT  14.784 34.476 14.808 34.56 ;
    END
  END rd_il[52]
  PIN rd_il[53]
    DIRECTION INPUT ;
    USE SIGNAL ;
    PORT
      LAYER M5 ;
        RECT  14.976 34.476 15 34.56 ;
    END
  END rd_il[53]
  PIN rd_il[54]
    DIRECTION INPUT ;
    USE SIGNAL ;
    PORT
      LAYER M5 ;
        RECT  15.168 34.476 15.192 34.56 ;
    END
  END rd_il[54]
  PIN rd_il[55]
    DIRECTION INPUT ;
    USE SIGNAL ;
    PORT
      LAYER M5 ;
        RECT  15.36 34.476 15.384 34.56 ;
    END
  END rd_il[55]
  PIN rd_il[56]
    DIRECTION INPUT ;
    USE SIGNAL ;
    PORT
      LAYER M5 ;
        RECT  15.552 34.476 15.576 34.56 ;
    END
  END rd_il[56]
  PIN rd_il[57]
    DIRECTION INPUT ;
    USE SIGNAL ;
    PORT
      LAYER M5 ;
        RECT  15.744 34.476 15.768 34.56 ;
    END
  END rd_il[57]
  PIN rd_il[58]
    DIRECTION INPUT ;
    USE SIGNAL ;
    PORT
      LAYER M5 ;
        RECT  15.936 34.476 15.96 34.56 ;
    END
  END rd_il[58]
  PIN rd_il[59]
    DIRECTION INPUT ;
    USE SIGNAL ;
    PORT
      LAYER M5 ;
        RECT  16.128 34.476 16.152 34.56 ;
    END
  END rd_il[59]
  PIN rd_il[5]
    DIRECTION INPUT ;
    USE SIGNAL ;
    PORT
      LAYER M5 ;
        RECT  5.76 34.476 5.784 34.56 ;
    END
  END rd_il[5]
  PIN rd_il[60]
    DIRECTION INPUT ;
    USE SIGNAL ;
    PORT
      LAYER M5 ;
        RECT  16.32 34.476 16.344 34.56 ;
    END
  END rd_il[60]
  PIN rd_il[61]
    DIRECTION INPUT ;
    USE SIGNAL ;
    PORT
      LAYER M5 ;
        RECT  16.512 34.476 16.536 34.56 ;
    END
  END rd_il[61]
  PIN rd_il[62]
    DIRECTION INPUT ;
    USE SIGNAL ;
    PORT
      LAYER M5 ;
        RECT  16.704 34.476 16.728 34.56 ;
    END
  END rd_il[62]
  PIN rd_il[63]
    DIRECTION INPUT ;
    USE SIGNAL ;
    PORT
      LAYER M5 ;
        RECT  16.896 34.476 16.92 34.56 ;
    END
  END rd_il[63]
  PIN rd_il[64]
    DIRECTION INPUT ;
    USE SIGNAL ;
    PORT
      LAYER M5 ;
        RECT  17.088 34.476 17.112 34.56 ;
    END
  END rd_il[64]
  PIN rd_il[65]
    DIRECTION INPUT ;
    USE SIGNAL ;
    PORT
      LAYER M5 ;
        RECT  17.28 34.476 17.304 34.56 ;
    END
  END rd_il[65]
  PIN rd_il[66]
    DIRECTION INPUT ;
    USE SIGNAL ;
    PORT
      LAYER M5 ;
        RECT  17.472 34.476 17.496 34.56 ;
    END
  END rd_il[66]
  PIN rd_il[67]
    DIRECTION INPUT ;
    USE SIGNAL ;
    PORT
      LAYER M5 ;
        RECT  17.664 34.476 17.688 34.56 ;
    END
  END rd_il[67]
  PIN rd_il[68]
    DIRECTION INPUT ;
    USE SIGNAL ;
    PORT
      LAYER M5 ;
        RECT  17.856 34.476 17.88 34.56 ;
    END
  END rd_il[68]
  PIN rd_il[69]
    DIRECTION INPUT ;
    USE SIGNAL ;
    PORT
      LAYER M5 ;
        RECT  18.048 34.476 18.072 34.56 ;
    END
  END rd_il[69]
  PIN rd_il[6]
    DIRECTION INPUT ;
    USE SIGNAL ;
    PORT
      LAYER M5 ;
        RECT  5.952 34.476 5.976 34.56 ;
    END
  END rd_il[6]
  PIN rd_il[70]
    DIRECTION INPUT ;
    USE SIGNAL ;
    PORT
      LAYER M5 ;
        RECT  18.24 34.476 18.264 34.56 ;
    END
  END rd_il[70]
  PIN rd_il[71]
    DIRECTION INPUT ;
    USE SIGNAL ;
    PORT
      LAYER M5 ;
        RECT  18.432 34.476 18.456 34.56 ;
    END
  END rd_il[71]
  PIN rd_il[72]
    DIRECTION INPUT ;
    USE SIGNAL ;
    PORT
      LAYER M5 ;
        RECT  18.624 34.476 18.648 34.56 ;
    END
  END rd_il[72]
  PIN rd_il[73]
    DIRECTION INPUT ;
    USE SIGNAL ;
    PORT
      LAYER M5 ;
        RECT  18.816 34.476 18.84 34.56 ;
    END
  END rd_il[73]
  PIN rd_il[74]
    DIRECTION INPUT ;
    USE SIGNAL ;
    PORT
      LAYER M5 ;
        RECT  19.008 34.476 19.032 34.56 ;
    END
  END rd_il[74]
  PIN rd_il[75]
    DIRECTION INPUT ;
    USE SIGNAL ;
    PORT
      LAYER M5 ;
        RECT  19.2 34.476 19.224 34.56 ;
    END
  END rd_il[75]
  PIN rd_il[76]
    DIRECTION INPUT ;
    USE SIGNAL ;
    PORT
      LAYER M5 ;
        RECT  19.392 34.476 19.416 34.56 ;
    END
  END rd_il[76]
  PIN rd_il[77]
    DIRECTION INPUT ;
    USE SIGNAL ;
    PORT
      LAYER M5 ;
        RECT  19.584 34.476 19.608 34.56 ;
    END
  END rd_il[77]
  PIN rd_il[78]
    DIRECTION INPUT ;
    USE SIGNAL ;
    PORT
      LAYER M5 ;
        RECT  19.776 34.476 19.8 34.56 ;
    END
  END rd_il[78]
  PIN rd_il[79]
    DIRECTION INPUT ;
    USE SIGNAL ;
    PORT
      LAYER M5 ;
        RECT  19.968 34.476 19.992 34.56 ;
    END
  END rd_il[79]
  PIN rd_il[7]
    DIRECTION INPUT ;
    USE SIGNAL ;
    PORT
      LAYER M5 ;
        RECT  6.144 34.476 6.168 34.56 ;
    END
  END rd_il[7]
  PIN rd_il[80]
    DIRECTION INPUT ;
    USE SIGNAL ;
    PORT
      LAYER M5 ;
        RECT  20.16 34.476 20.184 34.56 ;
    END
  END rd_il[80]
  PIN rd_il[81]
    DIRECTION INPUT ;
    USE SIGNAL ;
    PORT
      LAYER M5 ;
        RECT  20.352 34.476 20.376 34.56 ;
    END
  END rd_il[81]
  PIN rd_il[82]
    DIRECTION INPUT ;
    USE SIGNAL ;
    PORT
      LAYER M5 ;
        RECT  20.544 34.476 20.568 34.56 ;
    END
  END rd_il[82]
  PIN rd_il[83]
    DIRECTION INPUT ;
    USE SIGNAL ;
    PORT
      LAYER M5 ;
        RECT  20.736 34.476 20.76 34.56 ;
    END
  END rd_il[83]
  PIN rd_il[84]
    DIRECTION INPUT ;
    USE SIGNAL ;
    PORT
      LAYER M5 ;
        RECT  20.928 34.476 20.952 34.56 ;
    END
  END rd_il[84]
  PIN rd_il[85]
    DIRECTION INPUT ;
    USE SIGNAL ;
    PORT
      LAYER M5 ;
        RECT  21.12 34.476 21.144 34.56 ;
    END
  END rd_il[85]
  PIN rd_il[86]
    DIRECTION INPUT ;
    USE SIGNAL ;
    PORT
      LAYER M5 ;
        RECT  21.312 34.476 21.336 34.56 ;
    END
  END rd_il[86]
  PIN rd_il[87]
    DIRECTION INPUT ;
    USE SIGNAL ;
    PORT
      LAYER M5 ;
        RECT  21.504 34.476 21.528 34.56 ;
    END
  END rd_il[87]
  PIN rd_il[88]
    DIRECTION INPUT ;
    USE SIGNAL ;
    PORT
      LAYER M5 ;
        RECT  21.696 34.476 21.72 34.56 ;
    END
  END rd_il[88]
  PIN rd_il[89]
    DIRECTION INPUT ;
    USE SIGNAL ;
    PORT
      LAYER M5 ;
        RECT  21.888 34.476 21.912 34.56 ;
    END
  END rd_il[89]
  PIN rd_il[8]
    DIRECTION INPUT ;
    USE SIGNAL ;
    PORT
      LAYER M5 ;
        RECT  6.336 34.476 6.36 34.56 ;
    END
  END rd_il[8]
  PIN rd_il[90]
    DIRECTION INPUT ;
    USE SIGNAL ;
    PORT
      LAYER M5 ;
        RECT  22.08 34.476 22.104 34.56 ;
    END
  END rd_il[90]
  PIN rd_il[91]
    DIRECTION INPUT ;
    USE SIGNAL ;
    PORT
      LAYER M5 ;
        RECT  22.272 34.476 22.296 34.56 ;
    END
  END rd_il[91]
  PIN rd_il[92]
    DIRECTION INPUT ;
    USE SIGNAL ;
    PORT
      LAYER M5 ;
        RECT  22.464 34.476 22.488 34.56 ;
    END
  END rd_il[92]
  PIN rd_il[93]
    DIRECTION INPUT ;
    USE SIGNAL ;
    PORT
      LAYER M5 ;
        RECT  22.656 34.476 22.68 34.56 ;
    END
  END rd_il[93]
  PIN rd_il[94]
    DIRECTION INPUT ;
    USE SIGNAL ;
    PORT
      LAYER M5 ;
        RECT  22.848 34.476 22.872 34.56 ;
    END
  END rd_il[94]
  PIN rd_il[95]
    DIRECTION INPUT ;
    USE SIGNAL ;
    PORT
      LAYER M5 ;
        RECT  23.04 34.476 23.064 34.56 ;
    END
  END rd_il[95]
  PIN rd_il[96]
    DIRECTION INPUT ;
    USE SIGNAL ;
    PORT
      LAYER M5 ;
        RECT  23.232 34.476 23.256 34.56 ;
    END
  END rd_il[96]
  PIN rd_il[97]
    DIRECTION INPUT ;
    USE SIGNAL ;
    PORT
      LAYER M5 ;
        RECT  23.424 34.476 23.448 34.56 ;
    END
  END rd_il[97]
  PIN rd_il[98]
    DIRECTION INPUT ;
    USE SIGNAL ;
    PORT
      LAYER M5 ;
        RECT  23.616 34.476 23.64 34.56 ;
    END
  END rd_il[98]
  PIN rd_il[99]
    DIRECTION INPUT ;
    USE SIGNAL ;
    PORT
      LAYER M5 ;
        RECT  23.808 34.476 23.832 34.56 ;
    END
  END rd_il[99]
  PIN rd_il[9]
    DIRECTION INPUT ;
    USE SIGNAL ;
    PORT
      LAYER M5 ;
        RECT  6.528 34.476 6.552 34.56 ;
    END
  END rd_il[9]
  PIN sel[0]
    DIRECTION INPUT ;
    USE SIGNAL ;
    PORT
      LAYER M4 ;
        RECT  0 14.976 0.084 15 ;
    END
  END sel[0]
  PIN sel[10]
    DIRECTION INPUT ;
    USE SIGNAL ;
    PORT
      LAYER M4 ;
        RECT  0 16.896 0.084 16.92 ;
    END
  END sel[10]
  PIN sel[11]
    DIRECTION INPUT ;
    USE SIGNAL ;
    PORT
      LAYER M4 ;
        RECT  0 17.088 0.084 17.112 ;
    END
  END sel[11]
  PIN sel[12]
    DIRECTION INPUT ;
    USE SIGNAL ;
    PORT
      LAYER M4 ;
        RECT  0 17.28 0.084 17.304 ;
    END
  END sel[12]
  PIN sel[13]
    DIRECTION INPUT ;
    USE SIGNAL ;
    PORT
      LAYER M4 ;
        RECT  0 17.472 0.084 17.496 ;
    END
  END sel[13]
  PIN sel[14]
    DIRECTION INPUT ;
    USE SIGNAL ;
    PORT
      LAYER M4 ;
        RECT  0 17.664 0.084 17.688 ;
    END
  END sel[14]
  PIN sel[15]
    DIRECTION INPUT ;
    USE SIGNAL ;
    PORT
      LAYER M4 ;
        RECT  0 17.856 0.084 17.88 ;
    END
  END sel[15]
  PIN sel[16]
    DIRECTION INPUT ;
    USE SIGNAL ;
    PORT
      LAYER M4 ;
        RECT  0 18.048 0.084 18.072 ;
    END
  END sel[16]
  PIN sel[17]
    DIRECTION INPUT ;
    USE SIGNAL ;
    PORT
      LAYER M4 ;
        RECT  0 18.24 0.084 18.264 ;
    END
  END sel[17]
  PIN sel[18]
    DIRECTION INPUT ;
    USE SIGNAL ;
    PORT
      LAYER M4 ;
        RECT  0 18.432 0.084 18.456 ;
    END
  END sel[18]
  PIN sel[19]
    DIRECTION INPUT ;
    USE SIGNAL ;
    PORT
      LAYER M4 ;
        RECT  0 18.624 0.084 18.648 ;
    END
  END sel[19]
  PIN sel[1]
    DIRECTION INPUT ;
    USE SIGNAL ;
    PORT
      LAYER M4 ;
        RECT  0 15.168 0.084 15.192 ;
    END
  END sel[1]
  PIN sel[20]
    DIRECTION INPUT ;
    USE SIGNAL ;
    PORT
      LAYER M4 ;
        RECT  0 18.816 0.084 18.84 ;
    END
  END sel[20]
  PIN sel[21]
    DIRECTION INPUT ;
    USE SIGNAL ;
    PORT
      LAYER M4 ;
        RECT  0 19.008 0.084 19.032 ;
    END
  END sel[21]
  PIN sel[22]
    DIRECTION INPUT ;
    USE SIGNAL ;
    PORT
      LAYER M4 ;
        RECT  0 19.2 0.084 19.224 ;
    END
  END sel[22]
  PIN sel[23]
    DIRECTION INPUT ;
    USE SIGNAL ;
    PORT
      LAYER M4 ;
        RECT  0 19.392 0.084 19.416 ;
    END
  END sel[23]
  PIN sel[2]
    DIRECTION INPUT ;
    USE SIGNAL ;
    PORT
      LAYER M4 ;
        RECT  0 15.36 0.084 15.384 ;
    END
  END sel[2]
  PIN sel[3]
    DIRECTION INPUT ;
    USE SIGNAL ;
    PORT
      LAYER M4 ;
        RECT  0 15.552 0.084 15.576 ;
    END
  END sel[3]
  PIN sel[4]
    DIRECTION INPUT ;
    USE SIGNAL ;
    PORT
      LAYER M4 ;
        RECT  0 15.744 0.084 15.768 ;
    END
  END sel[4]
  PIN sel[5]
    DIRECTION INPUT ;
    USE SIGNAL ;
    PORT
      LAYER M4 ;
        RECT  0 15.936 0.084 15.96 ;
    END
  END sel[5]
  PIN sel[6]
    DIRECTION INPUT ;
    USE SIGNAL ;
    PORT
      LAYER M4 ;
        RECT  0 16.128 0.084 16.152 ;
    END
  END sel[6]
  PIN sel[7]
    DIRECTION INPUT ;
    USE SIGNAL ;
    PORT
      LAYER M4 ;
        RECT  0 16.32 0.084 16.344 ;
    END
  END sel[7]
  PIN sel[8]
    DIRECTION INPUT ;
    USE SIGNAL ;
    PORT
      LAYER M4 ;
        RECT  0 16.512 0.084 16.536 ;
    END
  END sel[8]
  PIN sel[9]
    DIRECTION INPUT ;
    USE SIGNAL ;
    PORT
      LAYER M4 ;
        RECT  0 16.704 0.084 16.728 ;
    END
  END sel[9]
  PIN VDD
    DIRECTION INOUT ;
    USE POWER ;
    PORT
      LAYER M5 ;
        RECT  32.292 2.151 32.412 32.409 ;
        RECT  29.592 2.151 29.712 32.409 ;
        RECT  26.892 2.151 27.012 32.409 ;
        RECT  24.192 2.151 24.312 32.409 ;
        RECT  21.492 2.151 21.612 32.409 ;
        RECT  18.792 2.151 18.912 32.409 ;
        RECT  16.092 2.151 16.212 32.409 ;
        RECT  13.392 2.151 13.512 32.409 ;
        RECT  10.692 2.151 10.812 32.409 ;
        RECT  7.992 2.151 8.112 32.409 ;
        RECT  5.292 2.151 5.412 32.409 ;
        RECT  2.592 2.151 2.712 32.409 ;
    END
  END VDD
  PIN VSS
    DIRECTION INOUT ;
    USE GROUND ;
    PORT
      LAYER M5 ;
        RECT  32.1 2.137 32.22 32.423 ;
        RECT  29.4 2.137 29.52 32.423 ;
        RECT  26.7 2.137 26.82 32.423 ;
        RECT  24 2.137 24.12 32.423 ;
        RECT  21.3 2.137 21.42 32.423 ;
        RECT  18.6 2.137 18.72 32.423 ;
        RECT  15.9 2.137 16.02 32.423 ;
        RECT  13.2 2.137 13.32 32.423 ;
        RECT  10.5 2.137 10.62 32.423 ;
        RECT  7.8 2.137 7.92 32.423 ;
        RECT  5.1 2.137 5.22 32.423 ;
        RECT  2.4 2.137 2.52 32.423 ;
    END
  END VSS
  # OT_OBS_CLOSED layer=M5 d_um=1.536 added=83
  OBS
    LAYER RVTN ;
     RECT  2.16 2.16 32.4 2.295 ;
     RECT  2.16 2.565 32.4 2.835 ;
     RECT  2.16 3.105 32.4 3.375 ;
     RECT  2.16 3.645 32.4 3.915 ;
     RECT  2.16 4.185 32.4 4.455 ;
     RECT  2.16 4.725 32.4 4.995 ;
     RECT  2.16 5.265 32.4 5.535 ;
     RECT  2.16 5.805 32.4 6.075 ;
     RECT  2.16 6.345 32.4 6.615 ;
     RECT  2.16 6.885 32.4 7.155 ;
     RECT  2.16 7.425 32.4 7.695 ;
     RECT  2.16 7.965 32.4 8.235 ;
     RECT  2.16 8.505 32.4 8.775 ;
     RECT  2.16 9.045 32.4 9.315 ;
     RECT  2.16 9.585 32.4 9.855 ;
     RECT  2.16 10.125 32.4 10.395 ;
     RECT  2.16 10.665 32.4 10.935 ;
     RECT  2.16 11.205 32.4 11.475 ;
     RECT  2.16 11.745 32.4 12.015 ;
     RECT  2.16 12.285 32.4 12.555 ;
     RECT  2.16 12.825 32.4 13.095 ;
     RECT  2.16 13.365 32.4 13.635 ;
     RECT  2.16 13.905 32.4 14.175 ;
     RECT  2.16 14.445 32.4 14.715 ;
     RECT  2.16 14.985 32.4 15.255 ;
     RECT  2.16 15.525 32.4 15.795 ;
     RECT  2.16 16.065 32.4 16.335 ;
     RECT  2.16 16.605 32.4 16.875 ;
     RECT  2.16 17.145 32.4 17.415 ;
     RECT  2.16 17.685 32.4 17.955 ;
     RECT  2.16 18.225 32.4 18.495 ;
     RECT  2.16 18.765 32.4 19.035 ;
     RECT  2.16 19.305 32.4 19.575 ;
     RECT  2.16 19.845 32.4 20.115 ;
     RECT  2.16 20.385 32.4 20.655 ;
     RECT  2.16 20.925 32.4 21.195 ;
     RECT  2.16 21.465 32.4 21.735 ;
     RECT  2.16 22.005 32.4 22.275 ;
     RECT  2.16 22.545 32.4 22.815 ;
     RECT  2.16 23.085 32.4 23.355 ;
     RECT  2.16 23.625 32.4 23.895 ;
     RECT  2.16 24.165 32.4 24.435 ;
     RECT  2.16 24.705 32.4 24.975 ;
     RECT  2.16 25.245 32.4 25.515 ;
     RECT  2.16 25.785 32.4 26.055 ;
     RECT  2.16 26.325 32.4 26.595 ;
     RECT  2.16 26.865 32.4 27.135 ;
     RECT  2.16 27.405 32.4 27.675 ;
     RECT  2.16 27.945 32.4 28.215 ;
     RECT  2.16 28.485 32.4 28.755 ;
     RECT  2.16 29.025 32.4 29.295 ;
     RECT  2.16 29.565 32.4 29.835 ;
     RECT  2.16 30.105 32.4 30.375 ;
     RECT  2.16 30.645 32.4 30.915 ;
     RECT  2.16 31.185 32.4 31.455 ;
     RECT  2.16 31.725 32.4 31.995 ;
     RECT  2.16 32.265 32.4 32.4 ;
    LAYER RVTP ;
     RECT  2.16 2.295 32.4 2.565 ;
     RECT  2.16 2.835 32.4 3.105 ;
     RECT  2.16 3.375 32.4 3.645 ;
     RECT  2.16 3.915 32.4 4.185 ;
     RECT  2.16 4.455 32.4 4.725 ;
     RECT  2.16 4.995 32.4 5.265 ;
     RECT  2.16 5.535 32.4 5.805 ;
     RECT  2.16 6.075 32.4 6.345 ;
     RECT  2.16 6.615 32.4 6.885 ;
     RECT  2.16 7.155 32.4 7.425 ;
     RECT  2.16 7.695 32.4 7.965 ;
     RECT  2.16 8.235 32.4 8.505 ;
     RECT  2.16 8.775 32.4 9.045 ;
     RECT  2.16 9.315 32.4 9.585 ;
     RECT  2.16 9.855 32.4 10.125 ;
     RECT  2.16 10.395 32.4 10.665 ;
     RECT  2.16 10.935 32.4 11.205 ;
     RECT  2.16 11.475 32.4 11.745 ;
     RECT  2.16 12.015 32.4 12.285 ;
     RECT  2.16 12.555 32.4 12.825 ;
     RECT  2.16 13.095 32.4 13.365 ;
     RECT  2.16 13.635 32.4 13.905 ;
     RECT  2.16 14.175 32.4 14.445 ;
     RECT  2.16 14.715 32.4 14.985 ;
     RECT  2.16 15.255 32.4 15.525 ;
     RECT  2.16 15.795 32.4 16.065 ;
     RECT  2.16 16.335 32.4 16.605 ;
     RECT  2.16 16.875 32.4 17.145 ;
     RECT  2.16 17.415 32.4 17.685 ;
     RECT  2.16 17.955 32.4 18.225 ;
     RECT  2.16 18.495 32.4 18.765 ;
     RECT  2.16 19.035 32.4 19.305 ;
     RECT  2.16 19.575 32.4 19.845 ;
     RECT  2.16 20.115 32.4 20.385 ;
     RECT  2.16 20.655 32.4 20.925 ;
     RECT  2.16 21.195 32.4 21.465 ;
     RECT  2.16 21.735 32.4 22.005 ;
     RECT  2.16 22.275 32.4 22.545 ;
     RECT  2.16 22.815 32.4 23.085 ;
     RECT  2.16 23.355 32.4 23.625 ;
     RECT  2.16 23.895 32.4 24.165 ;
     RECT  2.16 24.435 32.4 24.705 ;
     RECT  2.16 24.975 32.4 25.245 ;
     RECT  2.16 25.515 32.4 25.785 ;
     RECT  2.16 26.055 32.4 26.325 ;
     RECT  2.16 26.595 32.4 26.865 ;
     RECT  2.16 27.135 32.4 27.405 ;
     RECT  2.16 27.675 32.4 27.945 ;
     RECT  2.16 28.215 32.4 28.485 ;
     RECT  2.16 28.755 32.4 29.025 ;
     RECT  2.16 29.295 32.4 29.565 ;
     RECT  2.16 29.835 32.4 30.105 ;
     RECT  2.16 30.375 32.4 30.645 ;
     RECT  2.16 30.915 32.4 31.185 ;
     RECT  2.16 31.455 32.4 31.725 ;
     RECT  2.16 31.995 32.4 32.265 ;
    LAYER M1 ;
     RECT  2.16 2.151 32.4 32.409 ;
    LAYER M2 ;
     RECT  0.103 16.92 2.16 16.938 ;
     RECT  9.031 1.152 9.131 1.17 ;
     RECT  10.003 1.152 10.103 1.17 ;
     RECT  2.16 2.151 14.071 32.409 ;
     RECT  14.071 2.151 14.171 33.066 ;
     RECT  14.171 2.151 15.835 32.409 ;
     RECT  15.835 2.106 16.447 32.409 ;
     RECT  16.879 1.152 16.979 1.17 ;
     RECT  16.447 2.034 18.203 32.409 ;
     RECT  18.203 2.106 18.599 32.409 ;
     RECT  18.599 2.151 19.723 32.409 ;
     RECT  19.723 2.106 20.687 32.409 ;
     RECT  21.703 1.152 21.875 1.17 ;
     RECT  20.687 2.151 29.659 32.409 ;
     RECT  29.659 2.106 30.407 32.409 ;
     RECT  30.407 2.151 32.4 32.409 ;
     RECT  32.4 2.421 32.412 32.139 ;
    LAYER M3 ;
     RECT  19.476 0.091 19.494 0.139 ;
     RECT  21.204 0.091 21.906 0.139 ;
     RECT  25.632 0.091 25.794 0.139 ;
     RECT  27.216 0.091 27.234 0.139 ;
     RECT  28.296 0.043 28.314 0.139 ;
     RECT  14.076 0.091 16.398 0.187 ;
     RECT  17.172 0.091 17.19 0.187 ;
     RECT  21.204 0.139 22.194 0.187 ;
     RECT  27.216 0.139 27.414 0.187 ;
     RECT  28.296 0.139 28.35 0.187 ;
     RECT  10.908 0.091 10.926 0.235 ;
     RECT  11.916 0.091 11.934 0.235 ;
     RECT  8.172 0.091 9.054 0.523 ;
     RECT  14.076 0.187 17.19 0.523 ;
     RECT  19.404 0.139 19.494 0.523 ;
     RECT  24.876 0.091 24.894 0.523 ;
     RECT  25.632 0.139 26.118 0.523 ;
     RECT  27.216 0.187 28.35 0.523 ;
     RECT  5.58 0.091 5.598 0.571 ;
     RECT  21.132 0.187 22.194 0.571 ;
     RECT  4.644 0.091 4.662 1.051 ;
     RECT  5.58 0.571 6.174 1.051 ;
     RECT  7.272 0.523 7.29 1.147 ;
     RECT  10.008 0.139 10.026 1.147 ;
     RECT  19.404 0.523 19.962 1.147 ;
     RECT  24.876 0.523 26.118 1.147 ;
     RECT  10.008 1.147 10.17 1.175 ;
     RECT  21.132 0.571 22.734 1.675 ;
     RECT  4.644 1.051 6.174 1.723 ;
     RECT  7.092 1.147 7.29 1.723 ;
     RECT  10.908 0.235 11.934 1.723 ;
     RECT  13.14 1.099 13.158 1.723 ;
     RECT  14.076 0.523 17.874 1.723 ;
     RECT  18.756 1.147 19.962 1.723 ;
     RECT  20.916 1.675 22.734 1.723 ;
     RECT  29.304 0.571 29.322 1.723 ;
     RECT  29.304 1.723 29.574 1.771 ;
     RECT  26.856 0.523 28.35 1.819 ;
     RECT  29.304 1.771 29.682 1.819 ;
     RECT  4.644 1.723 7.398 2.011 ;
     RECT  8.172 0.523 9.198 2.011 ;
     RECT  24.84 1.147 26.118 2.011 ;
     RECT  26.856 1.819 29.682 2.101 ;
     RECT  10.044 1.175 10.17 2.143 ;
     RECT  10.908 1.723 13.158 2.143 ;
     RECT  24.372 2.011 26.118 2.143 ;
     RECT  26.856 2.101 30.402 2.143 ;
     RECT  4.644 2.011 9.198 2.191 ;
     RECT  10.044 2.143 13.305 2.191 ;
     RECT  14.076 1.723 22.734 2.191 ;
     RECT  24.015 2.143 30.402 2.191 ;
     RECT  4.644 2.191 30.402 2.263 ;
     RECT  4.644 2.263 30.438 2.371 ;
     RECT  2.415 2.143 2.505 2.413 ;
     RECT  32.115 2.143 32.205 2.413 ;
     RECT  4.464 2.371 30.69 2.525 ;
     RECT  4.716 2.525 30.69 2.569 ;
     RECT  4.716 2.569 31.374 3.839 ;
     RECT  4.716 3.839 31.23 3.875 ;
     RECT  4.716 3.875 31.086 3.955 ;
     RECT  4.572 3.955 31.086 4.109 ;
     RECT  4.572 4.109 30.726 4.379 ;
     RECT  4.572 4.379 30.69 4.495 ;
     RECT  4.032 4.495 30.69 4.541 ;
     RECT  4.824 4.541 30.69 4.685 ;
     RECT  5.076 4.685 30.69 4.919 ;
     RECT  5.076 4.919 30.474 7.627 ;
     RECT  4.788 7.627 30.474 8.437 ;
     RECT  4.464 8.437 30.474 8.477 ;
     RECT  4.608 8.477 30.474 9.787 ;
     RECT  4.14 9.787 30.474 10.741 ;
     RECT  3.888 10.741 30.474 10.781 ;
     RECT  4.212 10.781 30.474 11.705 ;
     RECT  4.212 11.705 5.526 11.899 ;
     RECT  3.816 11.899 5.526 12.487 ;
     RECT  6.264 11.705 30.474 12.487 ;
     RECT  3.816 12.487 30.474 12.821 ;
     RECT  2.415 2.413 2.697 12.865 ;
     RECT  2.415 12.865 3.078 12.901 ;
     RECT  3.816 12.821 17.442 12.901 ;
     RECT  2.415 12.901 17.442 13.639 ;
     RECT  18.252 12.821 30.474 13.639 ;
     RECT  2.415 13.639 30.474 14.405 ;
     RECT  2.415 14.405 17.442 14.971 ;
     RECT  2.304 14.971 17.442 15.187 ;
     RECT  2.304 15.187 17.478 15.295 ;
     RECT  18.288 14.405 30.474 15.295 ;
     RECT  0.108 15.835 0.126 15.965 ;
     RECT  34.452 17.275 34.47 17.453 ;
     RECT  0.108 16.915 0.126 17.885 ;
     RECT  2.304 15.295 30.474 18.419 ;
     RECT  2.304 18.419 30.438 18.464 ;
     RECT  2.34 18.464 30.438 19.195 ;
     RECT  2.304 19.195 30.438 19.345 ;
     RECT  2.304 19.345 31.014 19.387 ;
     RECT  2.268 19.387 31.014 19.535 ;
     RECT  2.304 19.535 31.014 19.805 ;
     RECT  2.376 19.805 31.014 21.119 ;
     RECT  2.415 21.119 31.014 22.073 ;
     RECT  3.672 22.073 31.014 22.469 ;
     RECT  4.14 22.469 31.014 22.775 ;
     RECT  4.176 22.775 31.014 23.279 ;
     RECT  4.284 23.279 31.014 23.549 ;
     RECT  4.608 23.549 31.014 23.819 ;
     RECT  4.752 23.819 31.014 23.855 ;
     RECT  4.824 23.855 31.014 24.089 ;
     RECT  5.076 24.089 31.014 24.233 ;
     RECT  5.115 24.233 31.014 25.205 ;
     RECT  9.468 25.205 31.014 29.029 ;
     RECT  5.115 25.205 8.586 29.371 ;
     RECT  9.432 29.029 31.014 29.371 ;
     RECT  5.115 29.371 31.014 29.759 ;
     RECT  5.115 29.759 30.474 30.721 ;
     RECT  4.968 30.721 30.474 30.875 ;
     RECT  5.04 30.875 30.474 31.109 ;
     RECT  5.04 31.109 30.294 31.919 ;
     RECT  5.04 31.919 29.79 32.071 ;
     RECT  2.415 22.073 2.697 32.147 ;
     RECT  32.115 2.413 32.397 32.147 ;
     RECT  4.752 32.071 29.79 32.189 ;
     RECT  22.176 32.189 29.574 32.237 ;
     RECT  15.66 32.189 16.254 32.297 ;
     RECT  4.752 32.189 13.305 32.305 ;
     RECT  15.84 32.297 16.254 32.369 ;
     RECT  2.415 32.147 2.505 32.417 ;
     RECT  4.572 32.305 13.305 32.417 ;
     RECT  15.84 32.369 16.005 32.417 ;
     RECT  16.992 32.189 21.405 32.417 ;
     RECT  22.176 32.237 29.505 32.417 ;
     RECT  32.115 32.147 32.205 32.417 ;
     RECT  7.956 32.417 13.158 32.429 ;
     RECT  22.176 32.417 29.07 32.429 ;
     RECT  4.572 32.417 7.182 32.477 ;
     RECT  7.956 32.429 11.646 32.477 ;
     RECT  12.42 32.429 13.158 32.477 ;
     RECT  16.992 32.417 21.222 32.477 ;
     RECT  22.176 32.429 28.998 32.477 ;
     RECT  5.256 32.477 5.526 32.525 ;
     RECT  7.956 32.477 8.334 32.525 ;
     RECT  12.528 32.477 13.158 32.525 ;
     RECT  18.036 32.477 18.954 32.525 ;
     RECT  26.496 32.477 27.198 32.525 ;
     RECT  5.256 32.525 5.274 32.573 ;
     RECT  7.956 32.525 7.974 32.573 ;
     RECT  10.368 32.477 10.386 32.573 ;
     RECT  15.84 32.417 15.894 32.573 ;
     RECT  18.036 32.525 18.594 32.573 ;
     RECT  23.94 32.477 23.958 32.573 ;
     RECT  26.496 32.525 26.514 32.573 ;
     RECT  14.148 32.189 14.166 33.043 ;
     RECT  14.076 33.043 14.166 33.071 ;
     RECT  14.076 33.071 14.094 33.101 ;
     RECT  15.84 32.573 15.858 33.101 ;
     RECT  19.908 32.477 21.222 33.101 ;
     RECT  12.528 32.525 12.546 33.629 ;
     RECT  19.908 33.101 20.898 33.629 ;
     RECT  6.696 32.477 6.714 33.677 ;
     RECT  20.484 33.629 20.502 33.677 ;
     RECT  22.68 32.477 22.698 33.677 ;
     RECT  11.376 32.477 11.502 34.349 ;
     RECT  11.484 34.349 11.502 34.445 ;
     RECT  16.992 32.477 17.01 34.445 ;
     RECT  18.036 32.573 18.054 34.445 ;
    LAYER M4 ;
     RECT  0.084 14.976 2.408 15 ;
     RECT  0.06 15 2.408 15.168 ;
     RECT  0.084 15.168 2.408 15.192 ;
     RECT  0.06 15.192 2.408 15.36 ;
     RECT  0.084 15.36 2.408 15.384 ;
     RECT  0.06 15.384 2.408 15.552 ;
     RECT  0.084 15.552 2.408 15.576 ;
     RECT  0.06 15.576 2.408 15.744 ;
     RECT  0.084 15.744 2.408 15.768 ;
     RECT  0.06 15.768 2.408 15.936 ;
     RECT  0.084 15.936 2.408 15.96 ;
     RECT  0.06 15.96 2.408 16.128 ;
     RECT  0.084 16.128 2.408 16.152 ;
     RECT  0.06 16.152 2.408 16.32 ;
     RECT  0.084 16.32 2.408 16.344 ;
     RECT  0.06 16.344 2.408 16.512 ;
     RECT  0.084 16.512 2.408 16.536 ;
     RECT  0.06 16.536 2.408 16.704 ;
     RECT  0.084 16.704 2.408 16.728 ;
     RECT  0.06 16.728 2.408 16.896 ;
     RECT  0.084 16.896 2.408 16.92 ;
     RECT  0.06 16.92 2.408 17.088 ;
     RECT  0.084 17.088 2.408 17.112 ;
     RECT  0.06 17.112 2.408 17.28 ;
     RECT  0.084 17.28 2.408 17.304 ;
     RECT  0.06 17.304 2.408 17.472 ;
     RECT  0.084 17.472 2.408 17.496 ;
     RECT  0.06 17.496 2.408 17.664 ;
     RECT  0.084 17.664 2.408 17.688 ;
     RECT  0.06 17.688 2.408 17.856 ;
     RECT  0.084 17.856 2.408 17.88 ;
     RECT  0.06 17.88 2.408 18.048 ;
     RECT  0.084 18.048 2.408 18.072 ;
     RECT  0.06 18.072 2.408 18.24 ;
     RECT  0.084 18.24 2.408 18.264 ;
     RECT  0.06 18.264 2.408 18.432 ;
     RECT  0.084 18.432 2.408 18.456 ;
     RECT  0.06 18.456 2.408 18.624 ;
     RECT  0.084 18.624 2.408 18.648 ;
     RECT  0.06 18.648 2.408 18.816 ;
     RECT  0.084 18.816 2.408 18.84 ;
     RECT  0.06 18.84 2.408 19.008 ;
     RECT  0.084 19.008 2.408 19.032 ;
     RECT  0.06 19.032 2.408 19.2 ;
     RECT  0.084 19.2 2.408 19.224 ;
     RECT  0.06 19.224 2.408 19.392 ;
     RECT  0.084 19.392 2.408 19.416 ;
     RECT  2.408 2.148 2.512 32.412 ;
     RECT  2.512 2.418 2.704 32.142 ;
     RECT  2.704 14.208 3.061 21.144 ;
     RECT  3.836 10.752 3.877 10.776 ;
     RECT  3.805 11.904 3.877 12.552 ;
     RECT  3.877 10.752 3.923 12.552 ;
     RECT  3.061 14.208 3.925 14.232 ;
     RECT  3.925 14.16 4.129 14.232 ;
     RECT  3.061 15.408 4.129 21.144 ;
     RECT  2.704 22.224 4.165 22.248 ;
     RECT  4.129 14.16 4.237 21.144 ;
     RECT  4.165 22.224 4.237 23.112 ;
     RECT  3.923 12.528 4.556 12.552 ;
     RECT  4.021 4.512 4.705 4.536 ;
     RECT  4.453 8.448 4.777 8.472 ;
     RECT  4.921 1.104 4.949 1.128 ;
     RECT  4.949 1.104 5.108 1.752 ;
     RECT  4.705 4.416 5.108 4.536 ;
     RECT  4.777 7.92 5.108 8.472 ;
     RECT  4.129 9.792 5.108 9.816 ;
     RECT  3.923 11.136 5.108 11.16 ;
     RECT  4.556 12.528 5.108 13.08 ;
     RECT  4.237 14.16 5.108 23.112 ;
     RECT  4.561 32.448 5.108 32.472 ;
     RECT  5.108 1.104 5.173 32.472 ;
     RECT  4.633 0.096 5.218 0.12 ;
     RECT  5.173 1.104 5.218 32.568 ;
     RECT  5.218 0.096 5.285 32.568 ;
     RECT  5.285 0.096 5.404 32.52 ;
     RECT  5.404 0.096 5.411 2.28 ;
     RECT  5.404 31.92 5.537 32.52 ;
     RECT  5.404 9.36 5.555 9.432 ;
     RECT  5.404 12.528 5.603 13.128 ;
     RECT  5.411 0.096 5.609 0.6 ;
     RECT  5.404 18.144 5.681 20.136 ;
     RECT  5.555 9.408 5.699 9.432 ;
     RECT  5.404 14.208 5.717 17.16 ;
     RECT  5.404 7.92 5.789 7.944 ;
     RECT  5.404 21.168 5.825 22.2 ;
     RECT  5.603 13.104 5.905 13.128 ;
     RECT  5.717 14.208 5.941 14.904 ;
     RECT  5.825 21.216 6.005 22.2 ;
     RECT  5.681 18.432 6.113 19.8 ;
     RECT  5.609 0.144 6.185 0.6 ;
     RECT  6.113 18.432 6.185 19.416 ;
     RECT  5.404 10.464 6.329 10.488 ;
     RECT  5.404 4.032 6.401 4.536 ;
     RECT  6.005 21.408 6.689 22.2 ;
     RECT  6.185 18.432 6.833 19.08 ;
     RECT  5.941 14.352 6.901 14.904 ;
     RECT  5.717 15.888 6.901 17.16 ;
     RECT  6.685 33.648 6.947 33.672 ;
     RECT  6.829 28.464 6.949 28.488 ;
     RECT  5.404 5.616 6.973 5.64 ;
     RECT  5.411 1.728 7.081 2.28 ;
     RECT  7.081 1.152 7.093 2.28 ;
     RECT  6.949 28.464 7.117 28.584 ;
     RECT  6.401 4.032 7.189 4.44 ;
     RECT  6.901 14.352 7.189 17.16 ;
     RECT  6.185 0.144 7.261 0.168 ;
     RECT  7.093 1.152 7.261 2.328 ;
     RECT  7.261 0.144 7.331 2.328 ;
     RECT  7.117 28.464 7.381 29.112 ;
     RECT  7.331 1.728 7.409 2.328 ;
     RECT  7.189 3.888 7.477 4.44 ;
     RECT  6.973 5.472 7.477 5.64 ;
     RECT  6.689 21.408 7.549 21.48 ;
     RECT  7.331 0.144 7.715 0.552 ;
     RECT  6.901 7.344 7.729 7.368 ;
     RECT  7.729 7.344 7.765 7.464 ;
     RECT  7.585 8.448 7.765 8.472 ;
     RECT  7.409 2.016 7.808 2.328 ;
     RECT  7.477 3.888 7.808 5.64 ;
     RECT  7.765 7.104 7.808 8.472 ;
     RECT  7.333 10.752 7.808 10.776 ;
     RECT  7.621 12 7.808 12.024 ;
     RECT  7.261 13.056 7.808 13.08 ;
     RECT  7.189 14.352 7.808 18.264 ;
     RECT  7.369 19.248 7.808 19.656 ;
     RECT  7.549 21.072 7.808 21.48 ;
     RECT  7.729 22.752 7.808 22.776 ;
     RECT  5.404 24.48 7.808 24.504 ;
     RECT  7.381 28.464 7.808 29.352 ;
     RECT  5.404 30.768 7.808 30.888 ;
     RECT  5.537 31.92 7.808 32.472 ;
     RECT  7.808 2.016 7.861 32.472 ;
     RECT  7.861 2.016 7.985 32.568 ;
     RECT  7.985 2.418 8.104 32.52 ;
     RECT  8.104 14.928 8.237 21.48 ;
     RECT  8.104 12 8.243 13.848 ;
     RECT  8.104 24.24 8.243 24.504 ;
     RECT  8.104 30.768 8.243 30.84 ;
     RECT  8.243 24.48 8.273 24.504 ;
     RECT  8.104 2.88 8.309 8.28 ;
     RECT  8.237 19.632 8.309 21.48 ;
     RECT  8.237 14.928 8.345 18.168 ;
     RECT  8.104 32.4 8.345 32.52 ;
     RECT  8.345 14.928 8.381 15.576 ;
     RECT  8.243 13.104 8.461 13.848 ;
     RECT  8.345 16.608 8.489 18.168 ;
     RECT  8.104 22.752 8.525 22.776 ;
     RECT  8.243 12 8.531 12.024 ;
     RECT  8.104 9.6 8.572 9.624 ;
     RECT  8.381 15.264 8.669 15.576 ;
     RECT  8.309 2.88 8.705 2.904 ;
     RECT  8.309 3.888 8.741 8.28 ;
     RECT  8.243 30.816 8.819 30.84 ;
     RECT  8.053 0.096 9.164 0.12 ;
     RECT  8.345 32.4 9.164 32.472 ;
     RECT  9.164 0.096 9.251 0.552 ;
     RECT  9.164 31.92 9.251 32.472 ;
     RECT  8.309 19.92 9.313 21.48 ;
     RECT  8.669 15.552 9.385 15.576 ;
     RECT  8.489 16.608 9.385 18.024 ;
     RECT  9.313 19.92 9.389 21.528 ;
     RECT  8.461 13.824 9.529 13.848 ;
     RECT  9.529 13.728 9.673 13.848 ;
     RECT  9.385 15.552 9.709 18.024 ;
     RECT  9.692 9.12 9.733 9.144 ;
     RECT  8.104 29.328 9.788 29.352 ;
     RECT  8.741 3.888 9.817 7.752 ;
     RECT  9.733 9.12 9.817 9.576 ;
     RECT  9.781 1.728 9.973 1.752 ;
     RECT  9.973 1.152 10.073 1.752 ;
     RECT  10.073 1.152 10.181 1.176 ;
     RECT  10.177 2.832 10.213 2.856 ;
     RECT  9.817 3.888 10.213 9.576 ;
     RECT  9.389 20.16 10.213 21.528 ;
     RECT  9.961 22.8 10.213 22.824 ;
     RECT  9.709 14.832 10.257 18.024 ;
     RECT  9.251 32.4 10.309 32.472 ;
     RECT  10.257 14.832 10.321 18.168 ;
     RECT  9.385 24.048 10.321 24.072 ;
     RECT  10.309 31.632 10.357 32.52 ;
     RECT  10.213 2.832 10.508 9.576 ;
     RECT  9.673 13.152 10.508 13.848 ;
     RECT  10.321 14.832 10.508 18.792 ;
     RECT  10.213 20.16 10.508 22.824 ;
     RECT  10.321 23.952 10.508 24.072 ;
     RECT  9.313 25.056 10.508 25.08 ;
     RECT  9.788 29.184 10.508 29.352 ;
     RECT  10.357 31.632 10.508 32.568 ;
     RECT  10.508 2.148 10.595 32.568 ;
     RECT  10.595 2.148 10.612 32.52 ;
     RECT  10.612 2.418 10.787 32.52 ;
     RECT  10.787 2.418 10.804 32.472 ;
     RECT  10.804 13.824 10.973 15.336 ;
     RECT  10.804 4.896 11.045 10.776 ;
     RECT  11.045 10.224 11.081 10.776 ;
     RECT  11.045 4.896 11.219 9.096 ;
     RECT  10.973 14.928 11.225 15.336 ;
     RECT  10.804 19.44 11.233 19.896 ;
     RECT  9.251 0.096 11.317 0.168 ;
     RECT  10.804 31.92 11.363 32.472 ;
     RECT  11.125 34.416 11.365 34.44 ;
     RECT  11.081 10.752 11.369 10.776 ;
     RECT  11.219 6.864 11.413 9.096 ;
     RECT  11.225 14.928 11.441 15.288 ;
     RECT  10.973 13.824 11.477 13.848 ;
     RECT  10.804 16.368 11.477 18.168 ;
     RECT  11.365 34.32 11.513 34.44 ;
     RECT  11.477 16.368 11.521 17.688 ;
     RECT  11.521 16.368 11.585 17.64 ;
     RECT  11.585 16.368 11.621 17.112 ;
     RECT  11.317 0.096 11.657 0.264 ;
     RECT  10.804 23.808 11.657 24.504 ;
     RECT  10.804 29.52 11.795 29.64 ;
     RECT  11.219 4.896 11.797 5.736 ;
     RECT  10.804 21.504 11.797 22.248 ;
     RECT  10.804 3.312 11.833 3.432 ;
     RECT  11.797 4.512 11.833 5.736 ;
     RECT  11.513 34.32 11.939 34.392 ;
     RECT  11.413 7.488 11.981 9.096 ;
     RECT  11.981 7.488 12.017 8.664 ;
     RECT  12.085 1.728 12.257 1.752 ;
     RECT  11.939 34.32 12.323 34.344 ;
     RECT  12.257 1.728 12.337 1.8 ;
     RECT  12.337 1.728 12.557 2.28 ;
     RECT  11.657 0.096 12.611 0.12 ;
     RECT  11.797 21.36 12.613 22.248 ;
     RECT  11.657 23.952 12.661 24.504 ;
     RECT  12.301 13.968 12.697 13.992 ;
     RECT  12.697 13.392 12.757 13.992 ;
     RECT  11.441 15.168 12.805 15.288 ;
     RECT  11.621 16.368 12.805 17.064 ;
     RECT  11.233 19.488 12.805 19.896 ;
     RECT  12.757 13.104 12.841 13.992 ;
     RECT  12.805 15.168 12.841 17.064 ;
     RECT  12.841 13.104 12.877 17.064 ;
     RECT  12.517 33.6 12.899 33.624 ;
     RECT  11.363 32.4 13.045 32.472 ;
     RECT  13.045 31.92 13.093 32.472 ;
     RECT  12.853 0.144 13.129 0.168 ;
     RECT  12.017 7.488 13.129 8.52 ;
     RECT  12.557 2.148 13.208 2.28 ;
     RECT  11.833 3.312 13.208 5.736 ;
     RECT  13.129 7.392 13.208 8.52 ;
     RECT  12.956 11.232 13.208 11.256 ;
     RECT  12.877 13.104 13.208 17.16 ;
     RECT  12.805 18.816 13.208 19.896 ;
     RECT  12.613 21.36 13.208 22.488 ;
     RECT  12.661 23.952 13.208 25.464 ;
     RECT  11.795 29.52 13.208 29.544 ;
     RECT  13.057 30.576 13.208 30.6 ;
     RECT  13.093 31.92 13.208 32.568 ;
     RECT  13.129 0.144 13.283 1.128 ;
     RECT  13.208 2.148 13.312 32.568 ;
     RECT  13.312 2.256 13.504 32.568 ;
     RECT  13.504 2.256 13.619 2.28 ;
     RECT  13.283 0.144 13.621 0.312 ;
     RECT  13.621 0.096 13.667 0.312 ;
     RECT  13.504 3.408 13.667 3.432 ;
     RECT  13.504 19.584 13.673 19.896 ;
     RECT  13.504 30.576 13.781 30.792 ;
     RECT  13.504 25.44 13.817 25.464 ;
     RECT  13.504 13.104 13.961 13.176 ;
     RECT  13.504 8.256 13.997 10.056 ;
     RECT  13.504 14.976 13.997 15.192 ;
     RECT  13.504 4.464 14.033 6.84 ;
     RECT  13.997 8.736 14.069 10.056 ;
     RECT  14.069 8.736 14.285 9.624 ;
     RECT  13.504 11.808 14.321 12.024 ;
     RECT  14.321 12 14.465 12.024 ;
     RECT  13.504 29.52 14.497 29.544 ;
     RECT  14.497 29.328 14.537 29.544 ;
     RECT  14.065 33.072 14.627 33.096 ;
     RECT  14.285 8.736 14.645 9.192 ;
     RECT  13.504 16.368 14.681 17.256 ;
     RECT  13.504 31.92 14.773 31.944 ;
     RECT  13.997 15.12 14.785 15.192 ;
     RECT  13.673 19.584 14.785 19.8 ;
     RECT  14.033 4.512 14.893 6.84 ;
     RECT  14.893 4.512 14.965 7.128 ;
     RECT  14.645 8.736 14.965 9.048 ;
     RECT  14.785 15.12 15.073 15.24 ;
     RECT  13.667 0.096 15.157 0.216 ;
     RECT  13.961 13.104 15.245 13.128 ;
     RECT  15.245 13.104 15.253 13.176 ;
     RECT  14.965 4.512 15.325 9.048 ;
     RECT  15.289 10.032 15.325 10.44 ;
     RECT  14.681 16.848 15.397 17.256 ;
     RECT  15.325 10.032 15.433 10.68 ;
     RECT  15.397 16.848 15.452 17.64 ;
     RECT  14.785 18.816 15.452 19.8 ;
     RECT  15.253 12.048 15.469 13.848 ;
     RECT  13.781 30.768 15.505 30.792 ;
     RECT  13.504 21.36 15.577 22.488 ;
     RECT  15.452 16.848 15.649 19.8 ;
     RECT  15.505 30.672 15.685 30.792 ;
     RECT  15.469 11.952 15.74 13.848 ;
     RECT  15.073 15.12 15.74 15.864 ;
     RECT  15.74 11.952 15.781 15.864 ;
     RECT  15.649 16.848 15.781 19.896 ;
     RECT  14.773 31.92 15.865 32.088 ;
     RECT  15.829 33.072 15.865 33.096 ;
     RECT  14.741 1.728 15.908 1.752 ;
     RECT  15.325 3.6 15.908 9.048 ;
     RECT  15.433 10.032 15.908 10.824 ;
     RECT  15.781 11.952 15.908 19.896 ;
     RECT  15.577 20.88 15.908 22.488 ;
     RECT  14.537 29.328 15.908 29.352 ;
     RECT  15.685 30.672 15.908 30.936 ;
     RECT  15.865 31.92 15.908 33.096 ;
     RECT  15.908 1.728 16.163 33.096 ;
     RECT  16.163 1.728 16.204 32.424 ;
     RECT  16.204 3.312 16.229 7.224 ;
     RECT  16.229 3.312 16.301 6.12 ;
     RECT  16.204 18.816 16.301 19.896 ;
     RECT  16.204 29.328 16.355 30.792 ;
     RECT  16.301 3.312 16.403 3.864 ;
     RECT  16.403 3.312 16.417 3.624 ;
     RECT  16.355 29.328 16.489 29.688 ;
     RECT  16.355 30.768 16.517 30.792 ;
     RECT  16.417 3.408 16.561 3.624 ;
     RECT  16.561 3.6 16.589 3.624 ;
     RECT  16.229 7.104 16.625 7.224 ;
     RECT  16.204 15.312 16.625 16.104 ;
     RECT  16.204 17.136 16.625 17.64 ;
     RECT  15.157 0.096 16.693 0.6 ;
     RECT  16.204 1.728 16.693 1.752 ;
     RECT  16.204 10.32 16.733 10.68 ;
     RECT  16.693 0.096 16.777 1.752 ;
     RECT  16.204 12.384 16.913 12.552 ;
     RECT  16.204 31.92 16.931 32.424 ;
     RECT  16.204 8.64 16.993 9.144 ;
     RECT  16.993 8.736 17.021 9.144 ;
     RECT  17.021 8.736 17.057 9 ;
     RECT  16.625 17.136 17.057 17.544 ;
     RECT  16.204 21.072 17.057 23.304 ;
     RECT  17.057 8.784 17.129 9 ;
     RECT  16.733 10.368 17.129 10.68 ;
     RECT  16.777 0.096 17.201 0.552 ;
     RECT  16.931 32.4 17.269 32.424 ;
     RECT  16.204 14.064 17.273 14.232 ;
     RECT  17.057 21.12 17.317 23.304 ;
     RECT  17.317 21.12 17.363 23.976 ;
     RECT  17.363 23.28 17.381 23.976 ;
     RECT  17.269 32.4 17.507 32.472 ;
     RECT  17.273 14.208 17.561 14.232 ;
     RECT  16.625 7.2 17.665 7.224 ;
     RECT  17.381 23.328 17.893 23.976 ;
     RECT  17.665 7.104 17.917 7.224 ;
     RECT  16.777 1.728 17.989 1.752 ;
     RECT  16.301 5.04 17.989 6.12 ;
     RECT  17.917 7.104 17.989 7.416 ;
     RECT  17.989 5.04 18.025 7.416 ;
     RECT  16.625 15.312 18.313 15.864 ;
     RECT  17.057 17.136 18.313 17.496 ;
     RECT  17.363 21.12 18.313 21.144 ;
     RECT  17.201 0.144 18.421 0.552 ;
     RECT  16.913 12.528 18.421 12.552 ;
     RECT  18.421 0.096 18.467 0.552 ;
     RECT  16.981 34.416 18.467 34.44 ;
     RECT  18.313 15.312 18.469 17.496 ;
     RECT  16.301 18.816 18.469 19.8 ;
     RECT  18.313 21.072 18.469 21.144 ;
     RECT  17.507 32.448 18.565 32.472 ;
     RECT  17.989 1.728 18.608 2.28 ;
     RECT  18.025 4.224 18.608 7.416 ;
     RECT  17.129 8.784 18.608 8.808 ;
     RECT  17.129 10.416 18.608 10.68 ;
     RECT  18.421 12.528 18.608 13.656 ;
     RECT  18.469 15.312 18.608 17.544 ;
     RECT  18.469 18.816 18.608 19.896 ;
     RECT  18.469 20.976 18.608 21.144 ;
     RECT  17.893 23.328 18.608 24.408 ;
     RECT  16.489 29.328 18.608 29.448 ;
     RECT  18.565 32.448 18.608 32.568 ;
     RECT  18.608 1.728 18.613 32.568 ;
     RECT  18.613 1.152 18.659 32.568 ;
     RECT  18.659 1.152 18.785 32.52 ;
     RECT  18.785 1.728 18.904 32.52 ;
     RECT  18.904 12.24 18.929 13.656 ;
     RECT  18.904 31.92 18.965 32.52 ;
     RECT  18.904 3.408 19.043 7.224 ;
     RECT  18.904 14.784 19.091 16.056 ;
     RECT  19.091 15.072 19.145 16.056 ;
     RECT  19.043 3.408 19.217 4.248 ;
     RECT  19.217 3.408 19.253 3.432 ;
     RECT  19.043 5.424 19.361 7.224 ;
     RECT  19.361 5.424 19.505 6.408 ;
     RECT  18.965 31.92 19.619 32.472 ;
     RECT  18.929 12.336 19.649 13.656 ;
     RECT  18.904 19.008 19.685 21.72 ;
     RECT  19.685 19.008 19.708 20.52 ;
     RECT  18.904 10.656 19.829 10.68 ;
     RECT  18.904 8.832 19.897 9.096 ;
     RECT  18.467 0.096 19.916 0.168 ;
     RECT  19.708 19.008 19.973 19.608 ;
     RECT  19.916 0.096 20.003 0.552 ;
     RECT  19.145 15.504 20.009 16.056 ;
     RECT  18.904 23.04 20.081 23.064 ;
     RECT  19.969 12.096 20.185 12.312 ;
     RECT  19.897 30.672 20.221 30.696 ;
     RECT  20.185 11.904 20.329 12.312 ;
     RECT  18.904 29.232 20.401 29.256 ;
     RECT  20.221 30.672 20.401 30.84 ;
     RECT  19.897 33.6 20.473 33.624 ;
     RECT  19.897 8.304 20.545 9.096 ;
     RECT  20.473 33.6 20.579 33.672 ;
     RECT  19.505 5.712 20.581 6.12 ;
     RECT  20.581 5.712 20.617 6.264 ;
     RECT  20.617 5.712 20.689 6.792 ;
     RECT  20.689 5.712 20.725 7.176 ;
     RECT  20.545 8.304 20.725 9.144 ;
     RECT  18.904 1.728 20.876 1.752 ;
     RECT  20.905 10.416 20.941 10.44 ;
     RECT  20.009 15.504 20.941 15.816 ;
     RECT  19.973 19.008 20.941 19.368 ;
     RECT  20.876 1.68 20.963 1.752 ;
     RECT  20.003 0.096 21.077 0.168 ;
     RECT  20.725 5.712 21.085 9.144 ;
     RECT  20.941 10.416 21.085 10.68 ;
     RECT  18.904 17.136 21.109 17.688 ;
     RECT  21.013 2.784 21.116 3.336 ;
     RECT  21.109 4.416 21.116 4.44 ;
     RECT  20.941 18.96 21.121 19.368 ;
     RECT  20.653 20.688 21.121 20.712 ;
     RECT  21.116 2.784 21.157 4.44 ;
     RECT  21.085 5.712 21.157 10.68 ;
     RECT  21.121 18.96 21.157 20.712 ;
     RECT  19.685 21.696 21.157 21.72 ;
     RECT  20.401 29.232 21.157 30.84 ;
     RECT  19.619 32.448 21.157 32.472 ;
     RECT  21.157 32.448 21.193 32.52 ;
     RECT  20.579 33.6 21.193 33.624 ;
     RECT  21.157 2.784 21.308 10.68 ;
     RECT  20.329 11.664 21.308 12.312 ;
     RECT  19.649 13.632 21.308 13.656 ;
     RECT  20.941 15.408 21.308 15.816 ;
     RECT  21.109 16.896 21.308 17.688 ;
     RECT  21.157 18.816 21.308 20.712 ;
     RECT  21.157 21.696 21.308 22.488 ;
     RECT  21.157 29.232 21.308 30.888 ;
     RECT  21.193 32.448 21.308 33.624 ;
     RECT  21.308 2.016 21.347 33.624 ;
     RECT  21.347 2.016 21.604 33.096 ;
     RECT  21.604 2.016 21.665 10.392 ;
     RECT  21.604 15.504 21.665 17.64 ;
     RECT  21.604 22.464 21.665 22.488 ;
     RECT  21.665 2.256 21.701 10.392 ;
     RECT  21.701 3.792 21.845 10.392 ;
     RECT  21.665 17.04 21.881 17.64 ;
     RECT  21.077 0.096 21.917 0.216 ;
     RECT  21.881 17.424 21.917 17.64 ;
     RECT  21.604 31.92 21.923 33.096 ;
     RECT  21.665 15.504 21.953 16.056 ;
     RECT  21.604 11.52 21.989 13.656 ;
     RECT  21.845 3.792 22.025 9.912 ;
     RECT  21.989 11.616 22.141 13.656 ;
     RECT  22.025 5.712 22.169 9.912 ;
     RECT  21.953 15.792 22.169 16.056 ;
     RECT  22.141 11.616 22.205 11.64 ;
     RECT  22.025 3.792 22.313 4.296 ;
     RECT  22.141 13.152 22.421 13.656 ;
     RECT  21.917 0.144 22.453 0.216 ;
     RECT  22.169 5.712 22.493 7.368 ;
     RECT  21.701 2.256 22.499 2.808 ;
     RECT  22.493 5.712 22.601 7.32 ;
     RECT  22.453 0.144 22.625 0.6 ;
     RECT  22.169 8.592 22.673 9.912 ;
     RECT  22.625 0.144 22.709 0.696 ;
     RECT  22.709 0.144 22.745 0.6 ;
     RECT  22.601 5.712 22.745 7.08 ;
     RECT  22.673 8.64 22.781 9.912 ;
     RECT  22.669 33.648 22.883 33.672 ;
     RECT  22.781 8.64 22.961 9.576 ;
     RECT  21.604 29.232 23.029 29.256 ;
     RECT  22.313 4.272 23.101 4.296 ;
     RECT  22.745 5.712 23.101 6.312 ;
     RECT  21.604 20.688 23.245 20.712 ;
     RECT  23.101 4.272 23.461 6.312 ;
     RECT  23.101 11.52 23.461 11.544 ;
     RECT  23.461 11.52 23.569 11.928 ;
     RECT  22.421 13.632 23.677 13.656 ;
     RECT  23.461 4.224 23.749 6.312 ;
     RECT  23.641 7.344 23.885 7.368 ;
     RECT  23.749 3.84 23.893 6.312 ;
     RECT  23.885 7.344 23.893 7.416 ;
     RECT  21.923 31.92 23.929 32.472 ;
     RECT  22.499 2.256 24.008 2.28 ;
     RECT  23.893 3.84 24.008 7.416 ;
     RECT  22.961 8.976 24.008 9.576 ;
     RECT  23.569 11.52 24.008 11.976 ;
     RECT  23.677 13.584 24.008 13.656 ;
     RECT  22.169 15.792 24.008 15.816 ;
     RECT  21.917 17.424 24.008 17.448 ;
     RECT  21.604 18.72 24.008 19.656 ;
     RECT  23.245 20.688 24.008 21 ;
     RECT  23.029 29.232 24.008 29.64 ;
     RECT  23.929 31.92 24.008 32.568 ;
     RECT  24.008 2.148 24.035 32.568 ;
     RECT  22.745 0.144 24.181 0.264 ;
     RECT  24.035 2.148 24.304 32.472 ;
     RECT  24.304 2.148 24.317 2.28 ;
     RECT  24.317 2.016 24.419 2.28 ;
     RECT  24.181 34.32 24.467 34.344 ;
     RECT  24.304 31.44 24.473 32.472 ;
     RECT  24.304 4.08 24.515 9.816 ;
     RECT  24.181 0.096 24.565 0.264 ;
     RECT  24.419 2.016 24.565 2.184 ;
     RECT  24.515 4.08 24.604 4.536 ;
     RECT  24.304 17.424 24.617 19.272 ;
     RECT  24.565 0.096 24.653 2.184 ;
     RECT  24.304 20.976 24.653 21 ;
     RECT  24.304 13.104 24.833 13.656 ;
     RECT  24.304 15.408 24.833 16.056 ;
     RECT  24.653 0.096 24.869 1.752 ;
     RECT  24.869 0.096 24.995 0.552 ;
     RECT  24.304 11.472 25.085 11.784 ;
     RECT  24.833 13.104 25.121 13.608 ;
     RECT  24.473 31.92 25.228 32.472 ;
     RECT  25.085 11.472 25.337 11.736 ;
     RECT  24.515 6.096 25.477 9.816 ;
     RECT  25.337 11.472 25.517 11.496 ;
     RECT  25.477 5.136 25.553 9.816 ;
     RECT  25.553 6.24 25.571 9.816 ;
     RECT  24.869 1.728 25.589 1.752 ;
     RECT  24.617 17.424 25.765 19.128 ;
     RECT  24.833 15.792 25.909 16.056 ;
     RECT  25.909 15.792 26.125 16.104 ;
     RECT  25.571 6.768 26.197 9.816 ;
     RECT  24.604 4.08 26.233 4.104 ;
     RECT  25.553 5.136 26.233 5.16 ;
     RECT  26.233 4.08 26.377 5.16 ;
     RECT  25.121 13.104 26.416 13.32 ;
     RECT  26.197 6.768 26.449 9.912 ;
     RECT  26.269 11.184 26.449 11.208 ;
     RECT  26.377 3.648 26.485 5.16 ;
     RECT  26.449 6.768 26.485 11.208 ;
     RECT  25.228 32.4 26.485 32.472 ;
     RECT  26.485 6.768 26.521 11.784 ;
     RECT  26.416 13.056 26.521 13.32 ;
     RECT  26.485 2.88 26.557 5.16 ;
     RECT  26.521 6.768 26.557 13.32 ;
     RECT  24.995 0.096 26.581 0.168 ;
     RECT  26.557 2.88 26.708 13.32 ;
     RECT  25.909 14.736 26.708 14.76 ;
     RECT  26.125 15.792 26.708 16.44 ;
     RECT  25.765 17.424 26.708 19.368 ;
     RECT  24.304 29.232 26.708 29.256 ;
     RECT  26.485 32.4 26.708 32.568 ;
     RECT  26.708 2.148 26.723 32.568 ;
     RECT  26.723 2.148 26.812 32.52 ;
     RECT  26.581 0.048 26.828 0.168 ;
     RECT  26.812 2.418 27.004 32.52 ;
     RECT  27.004 29.04 27.155 29.64 ;
     RECT  26.869 34.368 27.155 34.392 ;
     RECT  27.004 13.104 27.173 19.368 ;
     RECT  27.004 32.064 27.209 32.52 ;
     RECT  27.155 29.232 27.433 29.64 ;
     RECT  26.828 0.048 27.491 0.552 ;
     RECT  27.349 34.416 27.491 34.44 ;
     RECT  27.209 32.064 27.683 32.472 ;
     RECT  27.004 3.648 27.713 4.584 ;
     RECT  27.173 13.104 27.785 18.216 ;
     RECT  27.004 5.616 27.929 7.992 ;
     RECT  27.929 6.144 27.964 7.992 ;
     RECT  27.004 9.36 28.069 9.912 ;
     RECT  27.004 11.136 28.069 11.16 ;
     RECT  27.785 13.104 28.109 14.28 ;
     RECT  27.433 29.232 28.289 29.256 ;
     RECT  28.069 11.04 28.321 11.16 ;
     RECT  27.491 0.048 28.325 0.216 ;
     RECT  27.173 19.2 28.357 19.368 ;
     RECT  27.829 1.728 28.405 1.752 ;
     RECT  27.785 15.312 28.604 18.216 ;
     RECT  28.357 19.2 28.604 19.608 ;
     RECT  27.964 6.336 28.609 7.992 ;
     RECT  28.069 9.12 28.609 9.912 ;
     RECT  28.597 3.408 28.681 3.432 ;
     RECT  27.713 4.56 28.681 4.584 ;
     RECT  28.325 0.096 28.739 0.216 ;
     RECT  28.604 15.312 28.753 19.608 ;
     RECT  28.405 1.728 28.781 1.8 ;
     RECT  28.681 3.408 29.005 4.584 ;
     RECT  28.321 11.04 29.005 11.256 ;
     RECT  27.683 32.4 29.009 32.472 ;
     RECT  28.739 0.192 29.075 0.216 ;
     RECT  29.005 11.04 29.077 11.544 ;
     RECT  28.109 13.104 29.077 13.704 ;
     RECT  29.009 32.4 29.081 32.424 ;
     RECT  29.081 32.4 29.173 32.412 ;
     RECT  29.077 11.04 29.269 11.688 ;
     RECT  29.077 12.96 29.269 13.704 ;
     RECT  29.173 0.576 29.333 0.6 ;
     RECT  28.781 1.728 29.408 1.848 ;
     RECT  29.005 3.408 29.408 4.632 ;
     RECT  28.609 6.336 29.408 9.912 ;
     RECT  29.269 11.04 29.408 13.704 ;
     RECT  28.753 14.832 29.408 19.608 ;
     RECT  28.565 29.088 29.408 29.112 ;
     RECT  28.645 30.816 29.408 30.84 ;
     RECT  29.173 32.208 29.408 32.412 ;
     RECT  29.408 1.728 29.512 32.412 ;
     RECT  29.512 1.728 29.585 32.232 ;
     RECT  29.585 1.776 29.693 32.142 ;
     RECT  29.693 2.418 29.704 32.142 ;
     RECT  29.704 3.936 29.873 4.824 ;
     RECT  29.873 3.936 30.305 3.96 ;
     RECT  29.704 17.424 32.108 17.448 ;
     RECT  32.108 2.148 32.212 32.412 ;
     RECT  32.212 2.418 32.404 32.142 ;
     RECT  32.404 17.424 34.441 17.448 ;
    LAYER M5 ;
     RECT  4.824 0.016 4.992 0.084 ;
     RECT  5.016 0.016 5.184 0.084 ;
     RECT  5.208 0.016 5.376 0.084 ;
     RECT  5.4 0.016 5.568 0.084 ;
     RECT  5.592 0.016 5.76 0.084 ;
     RECT  5.784 0.016 5.952 0.084 ;
     RECT  5.976 0.016 6.144 0.084 ;
     RECT  6.168 0.016 6.336 0.084 ;
     RECT  6.36 0.016 6.528 0.084 ;
     RECT  6.552 0.016 6.72 0.084 ;
     RECT  6.744 0.016 6.912 0.084 ;
     RECT  6.936 0.016 7.104 0.084 ;
     RECT  7.128 0.016 7.296 0.084 ;
     RECT  7.32 0.016 7.488 0.084 ;
     RECT  7.512 0.016 7.68 0.084 ;
     RECT  7.704 0.016 7.872 0.084 ;
     RECT  7.896 0.016 8.064 0.084 ;
     RECT  8.088 0.016 8.256 0.084 ;
     RECT  8.28 0.016 8.448 0.084 ;
     RECT  8.472 0.016 8.64 0.084 ;
     RECT  8.664 0.016 8.832 0.084 ;
     RECT  8.856 0.016 9.024 0.084 ;
     RECT  9.048 0.016 9.216 0.084 ;
     RECT  9.24 0.016 9.408 0.084 ;
     RECT  9.432 0.016 9.6 0.084 ;
     RECT  9.624 0.016 9.792 0.084 ;
     RECT  9.816 0.016 9.984 0.084 ;
     RECT  10.008 0.016 10.176 0.084 ;
     RECT  10.2 0.016 10.368 0.084 ;
     RECT  10.392 0.016 10.56 0.084 ;
     RECT  10.584 0.016 10.752 0.084 ;
     RECT  10.776 0.016 10.944 0.084 ;
     RECT  10.968 0.016 11.136 0.084 ;
     RECT  11.16 0.016 11.328 0.084 ;
     RECT  11.352 0.016 11.52 0.084 ;
     RECT  11.544 0.016 11.712 0.084 ;
     RECT  11.736 0.016 11.904 0.084 ;
     RECT  11.928 0.016 12.096 0.084 ;
     RECT  12.12 0.016 12.288 0.084 ;
     RECT  12.312 0.016 12.48 0.084 ;
     RECT  12.504 0.016 12.672 0.084 ;
     RECT  12.696 0.016 12.864 0.084 ;
     RECT  12.888 0.016 13.056 0.084 ;
     RECT  13.08 0.016 13.248 0.084 ;
     RECT  13.272 0.016 13.44 0.084 ;
     RECT  13.464 0.016 13.632 0.084 ;
     RECT  13.656 0.016 13.824 0.084 ;
     RECT  13.848 0.016 14.016 0.084 ;
     RECT  14.04 0.016 14.208 0.084 ;
     RECT  14.232 0.016 14.4 0.084 ;
     RECT  14.424 0.016 14.592 0.084 ;
     RECT  14.616 0.016 14.784 0.084 ;
     RECT  14.808 0.016 14.976 0.084 ;
     RECT  15 0.016 15.168 0.084 ;
     RECT  15.192 0.016 15.36 0.084 ;
     RECT  15.384 0.016 15.552 0.084 ;
     RECT  15.576 0.016 15.744 0.084 ;
     RECT  15.768 0.016 15.936 0.084 ;
     RECT  15.96 0.016 16.128 0.084 ;
     RECT  16.152 0.016 16.32 0.084 ;
     RECT  16.344 0.016 16.512 0.084 ;
     RECT  16.536 0.016 16.704 0.084 ;
     RECT  16.728 0.016 16.896 0.084 ;
     RECT  16.92 0.016 17.088 0.084 ;
     RECT  17.112 0.016 17.28 0.084 ;
     RECT  17.304 0.016 17.472 0.084 ;
     RECT  17.496 0.016 17.664 0.084 ;
     RECT  17.688 0.016 17.856 0.084 ;
     RECT  17.88 0.016 18.048 0.084 ;
     RECT  18.072 0.016 18.24 0.084 ;
     RECT  18.264 0.016 18.432 0.084 ;
     RECT  18.456 0.016 18.624 0.084 ;
     RECT  18.648 0.016 18.816 0.084 ;
     RECT  18.84 0.016 19.008 0.084 ;
     RECT  19.032 0.016 19.2 0.084 ;
     RECT  19.224 0.016 19.392 0.084 ;
     RECT  19.416 0.016 19.584 0.084 ;
     RECT  19.608 0.016 19.776 0.084 ;
     RECT  19.8 0.016 19.968 0.084 ;
     RECT  19.992 0.016 20.16 0.084 ;
     RECT  20.184 0.016 20.352 0.084 ;
     RECT  20.376 0.016 20.544 0.084 ;
     RECT  20.568 0.016 20.736 0.084 ;
     RECT  20.76 0.016 20.928 0.084 ;
     RECT  20.952 0.016 21.12 0.084 ;
     RECT  21.144 0.016 21.312 0.084 ;
     RECT  21.336 0.016 21.504 0.084 ;
     RECT  21.528 0.016 21.696 0.084 ;
     RECT  21.72 0.016 21.888 0.084 ;
     RECT  21.912 0.016 22.08 0.084 ;
     RECT  22.104 0.016 22.272 0.084 ;
     RECT  22.296 0.016 22.464 0.084 ;
     RECT  22.488 0.016 22.656 0.084 ;
     RECT  22.68 0.016 22.848 0.084 ;
     RECT  22.872 0.016 23.04 0.084 ;
     RECT  23.064 0.016 23.232 0.084 ;
     RECT  23.256 0.016 23.424 0.084 ;
     RECT  23.448 0.016 23.616 0.084 ;
     RECT  23.64 0.016 23.808 0.084 ;
     RECT  23.832 0.016 24 0.084 ;
     RECT  24.024 0.016 24.192 0.084 ;
     RECT  24.216 0.016 24.384 0.084 ;
     RECT  24.408 0.016 24.576 0.084 ;
     RECT  24.6 0.016 24.768 0.084 ;
     RECT  24.792 0.016 24.96 0.084 ;
     RECT  24.984 0.016 25.152 0.084 ;
     RECT  25.176 0.016 25.344 0.084 ;
     RECT  25.368 0.016 25.536 0.084 ;
     RECT  25.56 0.016 25.728 0.084 ;
     RECT  25.752 0.016 25.92 0.084 ;
     RECT  25.944 0.016 26.112 0.084 ;
     RECT  26.136 0.016 26.304 0.084 ;
     RECT  26.328 0.016 26.496 0.084 ;
     RECT  26.52 0.016 26.688 0.084 ;
     RECT  26.712 0.016 26.88 0.084 ;
     RECT  26.904 0.016 27.072 0.084 ;
     RECT  27.096 0.016 27.264 0.084 ;
     RECT  27.288 0.016 27.456 0.084 ;
     RECT  27.48 0.016 27.648 0.084 ;
     RECT  27.672 0.016 27.84 0.084 ;
     RECT  27.864 0.016 28.032 0.084 ;
     RECT  28.056 0.016 28.224 0.084 ;
     RECT  28.248 0.016 28.416 0.084 ;
     RECT  28.44 0.016 28.608 0.084 ;
     RECT  28.632 0.016 28.8 0.084 ;
     RECT  28.824 0.016 28.992 0.084 ;
     RECT  29.016 0.016 29.184 0.084 ;
     RECT  4.8 0.084 29.208 0.131 ;
     RECT  4.992 0.131 29.208 0.563 ;
     RECT  27.84 0.563 29.208 0.611 ;
     RECT  4.992 0.563 8.664 1.763 ;
     RECT  9.792 0.563 26.52 1.763 ;
     RECT  27.84 0.611 29.064 1.763 ;
     RECT  28.416 1.763 29.064 1.811 ;
     RECT  26.304 1.763 26.52 2.137 ;
     RECT  28.608 1.811 29.064 2.137 ;
     RECT  2.4 2.137 2.52 2.151 ;
     RECT  26.304 2.137 26.82 2.151 ;
     RECT  28.608 2.137 29.52 2.151 ;
     RECT  32.1 2.137 32.22 2.151 ;
     RECT  5.1 1.763 8.664 2.291 ;
     RECT  7.104 2.291 8.664 2.339 ;
     RECT  7.44 2.339 8.664 2.915 ;
     RECT  10.176 1.763 16.536 3.443 ;
     RECT  28.608 2.151 29.712 3.443 ;
     RECT  12.576 3.443 16.392 3.875 ;
     RECT  7.44 2.915 8.28 3.877 ;
     RECT  7.44 3.877 8.424 4.019 ;
     RECT  10.176 3.443 11.4 4.501 ;
     RECT  12.576 3.875 16.212 4.501 ;
     RECT  17.664 1.763 24.504 4.501 ;
     RECT  26.304 2.151 27.012 4.549 ;
     RECT  28.704 3.443 29.712 4.549 ;
     RECT  26.304 4.549 29.712 4.595 ;
     RECT  7.488 4.019 8.424 4.643 ;
     RECT  10.176 4.501 16.212 5.029 ;
     RECT  17.664 4.501 24.552 5.029 ;
     RECT  10.176 5.029 24.552 5.123 ;
     RECT  12.576 5.123 24.552 5.171 ;
     RECT  12.672 5.171 24.552 5.219 ;
     RECT  12.72 5.219 24.552 5.267 ;
     RECT  5.1 2.291 5.412 5.605 ;
     RECT  10.176 5.123 11.4 5.747 ;
     RECT  17.664 5.267 24.552 5.747 ;
     RECT  21.024 5.747 24.552 5.795 ;
     RECT  21.024 5.795 22.632 5.891 ;
     RECT  26.4 4.595 29.712 6.229 ;
     RECT  10.32 5.747 11.4 6.323 ;
     RECT  12.72 5.267 16.212 6.323 ;
     RECT  24 5.795 24.552 6.757 ;
     RECT  25.536 6.229 29.712 6.757 ;
     RECT  10.5 6.323 11.4 6.899 ;
     RECT  21.024 5.891 22.104 6.995 ;
     RECT  15.264 6.323 16.212 7.189 ;
     RECT  23.904 6.757 29.712 7.427 ;
     RECT  24 7.427 29.712 8.003 ;
     RECT  15.264 7.189 16.344 8.629 ;
     RECT  15.264 8.629 16.968 9.059 ;
     RECT  10.5 6.899 11.208 9.109 ;
     RECT  5.1 5.605 5.544 9.397 ;
     RECT  9.744 9.109 11.208 9.587 ;
     RECT  7.584 4.643 8.424 9.589 ;
     RECT  5.1 9.397 5.688 10.453 ;
     RECT  3.888 10.741 3.912 11.939 ;
     RECT  24 8.003 25.08 11.941 ;
     RECT  7.584 9.589 8.52 12.035 ;
     RECT  21.12 6.995 22.104 12.563 ;
     RECT  5.1 10.453 5.88 13.045 ;
     RECT  4.608 13.045 5.88 13.139 ;
     RECT  7.584 12.035 8.424 13.139 ;
     RECT  10.5 9.587 11.208 13.141 ;
     RECT  15.264 9.059 16.212 13.187 ;
     RECT  4.608 13.139 5.592 14.149 ;
     RECT  2.4 2.151 2.712 14.197 ;
     RECT  3.936 14.149 5.592 14.197 ;
     RECT  7.584 13.139 8.328 14.485 ;
     RECT  18.336 5.747 19.032 14.773 ;
     RECT  2.4 14.197 5.928 14.867 ;
     RECT  7.104 14.485 8.328 15.301 ;
     RECT  18.336 14.773 19.08 15.493 ;
     RECT  23.616 11.941 25.08 15.827 ;
     RECT  26.4 8.003 29.712 16.019 ;
     RECT  9.888 13.141 11.208 16.355 ;
     RECT  10.5 16.355 11.208 16.357 ;
     RECT  2.4 14.867 5.688 16.595 ;
     RECT  12.72 6.323 14.232 16.595 ;
     RECT  18.336 15.493 19.176 16.595 ;
     RECT  7.104 15.301 8.52 16.643 ;
     RECT  2.4 16.595 5.592 16.835 ;
     RECT  12.72 16.595 13.512 16.979 ;
     RECT  2.4 16.835 5.544 17.171 ;
     RECT  18.384 16.595 19.176 17.171 ;
     RECT  21.12 12.563 21.612 17.221 ;
     RECT  10.5 16.357 11.496 17.317 ;
     RECT  28.8 16.019 29.712 17.317 ;
     RECT  20.208 17.221 21.612 17.459 ;
     RECT  28.704 17.317 29.712 17.461 ;
     RECT  15.456 13.187 16.212 17.605 ;
     RECT  7.584 16.643 8.52 17.699 ;
     RECT  10.272 17.317 11.496 17.699 ;
     RECT  24 15.827 25.08 17.699 ;
     RECT  10.272 17.699 11.208 18.179 ;
     RECT  26.4 16.019 27.012 18.181 ;
     RECT  28.608 17.461 29.712 18.181 ;
     RECT  7.68 17.699 8.52 18.275 ;
     RECT  24 17.699 25.032 18.563 ;
     RECT  26.4 18.181 29.712 18.709 ;
     RECT  12.816 16.979 13.512 18.851 ;
     RECT  18.384 17.171 18.912 18.851 ;
     RECT  21.168 17.459 21.612 18.851 ;
     RECT  15.408 17.605 16.212 19.093 ;
     RECT  17.232 18.997 17.256 19.093 ;
     RECT  25.776 18.709 29.712 19.235 ;
     RECT  2.4 17.171 5.412 19.283 ;
     RECT  15.408 19.093 17.256 19.331 ;
     RECT  25.776 19.235 27.012 19.379 ;
     RECT  10.368 18.179 11.208 19.475 ;
     RECT  13.104 18.851 13.512 19.619 ;
     RECT  18.6 18.851 18.912 19.861 ;
     RECT  21.3 18.851 21.612 19.909 ;
     RECT  3.744 19.283 5.412 20.003 ;
     RECT  3.936 20.003 5.412 20.195 ;
     RECT  18.48 19.861 18.912 20.485 ;
     RECT  10.368 19.475 10.812 20.579 ;
     RECT  18.48 20.485 19.656 21.011 ;
     RECT  7.8 18.275 8.52 21.061 ;
     RECT  4.752 20.195 5.412 21.251 ;
     RECT  13.2 19.619 13.512 21.493 ;
     RECT  15.408 19.331 17.16 21.637 ;
     RECT  18.6 21.011 19.656 21.731 ;
     RECT  15.408 21.637 17.352 22.259 ;
     RECT  21.168 19.909 21.612 22.499 ;
     RECT  4.8 21.251 5.412 23.123 ;
     RECT  15.9 22.259 17.352 23.893 ;
     RECT  18.6 21.731 18.912 23.893 ;
     RECT  12.624 21.493 13.512 23.987 ;
     RECT  15.9 23.893 18.912 23.987 ;
     RECT  7.8 21.061 8.808 24.469 ;
     RECT  10.5 20.579 10.812 25.045 ;
     RECT  6.96 24.469 8.808 28.595 ;
     RECT  26.7 19.379 27.012 29.029 ;
     RECT  28.608 19.235 29.712 29.123 ;
     RECT  9.84 25.045 10.812 29.219 ;
     RECT  7.392 28.595 8.808 29.363 ;
     RECT  17.616 23.987 18.912 29.363 ;
     RECT  17.904 29.363 18.912 29.459 ;
     RECT  10.5 29.219 10.812 29.605 ;
     RECT  24 18.563 24.312 29.605 ;
     RECT  26.7 29.029 27.144 29.605 ;
     RECT  21.3 22.499 21.612 30.709 ;
     RECT  7.8 29.363 8.808 30.757 ;
     RECT  15.9 23.987 16.488 30.803 ;
     RECT  6.864 30.757 8.808 30.851 ;
     RECT  28.656 29.123 29.712 30.851 ;
     RECT  6.864 30.851 8.112 30.899 ;
     RECT  15.9 30.803 16.212 30.901 ;
     RECT  23.04 29.605 24.312 31.429 ;
     RECT  10.5 29.605 11.784 31.621 ;
     RECT  5.1 23.123 5.412 31.909 ;
     RECT  7.8 30.899 8.112 31.909 ;
     RECT  13.2 23.987 13.512 31.909 ;
     RECT  15.744 30.901 16.212 31.909 ;
     RECT  18.6 29.459 18.912 31.909 ;
     RECT  21.12 30.709 21.612 31.909 ;
     RECT  23.04 31.429 24.456 31.909 ;
     RECT  26.7 29.605 27.384 32.053 ;
     RECT  29.4 30.851 29.712 32.197 ;
     RECT  5.1 31.909 8.112 32.389 ;
     RECT  9.216 31.909 9.24 32.389 ;
     RECT  10.32 31.621 11.784 32.389 ;
     RECT  13.056 31.909 16.92 32.389 ;
     RECT  21.12 31.909 25.176 32.389 ;
     RECT  26.7 32.053 27.672 32.389 ;
     RECT  29.184 32.197 29.712 32.389 ;
     RECT  2.4 19.283 2.712 32.409 ;
     RECT  21.12 32.389 29.712 32.409 ;
     RECT  32.1 2.151 32.412 32.409 ;
     RECT  2.4 32.409 2.52 32.423 ;
     RECT  21.12 32.409 29.52 32.423 ;
     RECT  32.1 32.409 32.22 32.423 ;
     RECT  5.1 32.389 17.496 32.437 ;
     RECT  18.6 31.909 19.608 32.437 ;
     RECT  21.12 32.423 29.208 32.437 ;
     RECT  4.8 32.437 29.208 34.476 ;
     RECT  4.824 34.476 4.992 34.512 ;
     RECT  5.016 34.476 5.184 34.512 ;
     RECT  5.208 34.476 5.376 34.512 ;
     RECT  5.4 34.476 5.568 34.512 ;
     RECT  5.592 34.476 5.76 34.512 ;
     RECT  5.784 34.476 5.952 34.512 ;
     RECT  5.976 34.476 6.144 34.512 ;
     RECT  6.168 34.476 6.336 34.512 ;
     RECT  6.36 34.476 6.528 34.512 ;
     RECT  6.552 34.476 6.72 34.512 ;
     RECT  6.744 34.476 6.912 34.512 ;
     RECT  6.936 34.476 7.104 34.512 ;
     RECT  7.128 34.476 7.296 34.512 ;
     RECT  7.32 34.476 7.488 34.512 ;
     RECT  7.512 34.476 7.68 34.512 ;
     RECT  7.704 34.476 7.872 34.512 ;
     RECT  7.896 34.476 8.064 34.512 ;
     RECT  8.088 34.476 8.256 34.512 ;
     RECT  8.28 34.476 8.448 34.512 ;
     RECT  8.472 34.476 8.64 34.512 ;
     RECT  8.664 34.476 8.832 34.512 ;
     RECT  8.856 34.476 9.024 34.512 ;
     RECT  9.048 34.476 9.216 34.512 ;
     RECT  9.24 34.476 9.408 34.512 ;
     RECT  9.432 34.476 9.6 34.512 ;
     RECT  9.624 34.476 9.792 34.512 ;
     RECT  9.816 34.476 9.984 34.512 ;
     RECT  10.008 34.476 10.176 34.512 ;
     RECT  10.2 34.476 10.368 34.512 ;
     RECT  10.392 34.476 10.56 34.512 ;
     RECT  10.584 34.476 10.752 34.512 ;
     RECT  10.776 34.476 10.944 34.512 ;
     RECT  10.968 34.476 11.136 34.512 ;
     RECT  11.16 34.476 11.328 34.512 ;
     RECT  11.352 34.476 11.52 34.512 ;
     RECT  11.544 34.476 11.712 34.512 ;
     RECT  11.736 34.476 11.904 34.512 ;
     RECT  11.928 34.476 12.096 34.512 ;
     RECT  12.12 34.476 12.288 34.512 ;
     RECT  12.312 34.476 12.48 34.512 ;
     RECT  12.504 34.476 12.672 34.512 ;
     RECT  12.696 34.476 12.864 34.512 ;
     RECT  12.888 34.476 13.056 34.512 ;
     RECT  13.08 34.476 13.248 34.512 ;
     RECT  13.272 34.476 13.44 34.512 ;
     RECT  13.464 34.476 13.632 34.512 ;
     RECT  13.656 34.476 13.824 34.512 ;
     RECT  13.848 34.476 14.016 34.512 ;
     RECT  14.04 34.476 14.208 34.512 ;
     RECT  14.232 34.476 14.4 34.512 ;
     RECT  14.424 34.476 14.592 34.512 ;
     RECT  14.616 34.476 14.784 34.512 ;
     RECT  14.808 34.476 14.976 34.512 ;
     RECT  15 34.476 15.168 34.512 ;
     RECT  15.192 34.476 15.36 34.512 ;
     RECT  15.384 34.476 15.552 34.512 ;
     RECT  15.576 34.476 15.744 34.512 ;
     RECT  15.768 34.476 15.936 34.512 ;
     RECT  15.96 34.476 16.128 34.512 ;
     RECT  16.152 34.476 16.32 34.512 ;
     RECT  16.344 34.476 16.512 34.512 ;
     RECT  16.536 34.476 16.704 34.512 ;
     RECT  16.728 34.476 16.896 34.512 ;
     RECT  16.92 34.476 17.088 34.512 ;
     RECT  17.112 34.476 17.28 34.512 ;
     RECT  17.304 34.476 17.472 34.512 ;
     RECT  17.496 34.476 17.664 34.512 ;
     RECT  17.688 34.476 17.856 34.512 ;
     RECT  17.88 34.476 18.048 34.512 ;
     RECT  18.072 34.476 18.24 34.512 ;
     RECT  18.264 34.476 18.432 34.512 ;
     RECT  18.456 34.476 18.624 34.512 ;
     RECT  18.648 34.476 18.816 34.512 ;
     RECT  18.84 34.476 19.008 34.512 ;
     RECT  19.032 34.476 19.2 34.512 ;
     RECT  19.224 34.476 19.392 34.512 ;
     RECT  19.416 34.476 19.584 34.512 ;
     RECT  19.608 34.476 19.776 34.512 ;
     RECT  19.8 34.476 19.968 34.512 ;
     RECT  19.992 34.476 20.16 34.512 ;
     RECT  20.184 34.476 20.352 34.512 ;
     RECT  20.376 34.476 20.544 34.512 ;
     RECT  20.568 34.476 20.736 34.512 ;
     RECT  20.76 34.476 20.928 34.512 ;
     RECT  20.952 34.476 21.12 34.512 ;
     RECT  21.144 34.476 21.312 34.512 ;
     RECT  21.336 34.476 21.504 34.512 ;
     RECT  21.528 34.476 21.696 34.512 ;
     RECT  21.72 34.476 21.888 34.512 ;
     RECT  21.912 34.476 22.08 34.512 ;
     RECT  22.104 34.476 22.272 34.512 ;
     RECT  22.296 34.476 22.464 34.512 ;
     RECT  22.488 34.476 22.656 34.512 ;
     RECT  22.68 34.476 22.848 34.512 ;
     RECT  22.872 34.476 23.04 34.512 ;
     RECT  23.064 34.476 23.232 34.512 ;
     RECT  23.256 34.476 23.424 34.512 ;
     RECT  23.448 34.476 23.616 34.512 ;
     RECT  23.64 34.476 23.808 34.512 ;
     RECT  23.832 34.476 24 34.512 ;
     RECT  24.024 34.476 24.192 34.512 ;
     RECT  24.216 34.476 24.384 34.512 ;
     RECT  24.408 34.476 24.576 34.512 ;
     RECT  24.6 34.476 24.768 34.512 ;
     RECT  24.792 34.476 24.96 34.512 ;
     RECT  24.984 34.476 25.152 34.512 ;
     RECT  25.176 34.476 25.344 34.512 ;
     RECT  25.368 34.476 25.536 34.512 ;
     RECT  25.56 34.476 25.728 34.512 ;
     RECT  25.752 34.476 25.92 34.512 ;
     RECT  25.944 34.476 26.112 34.512 ;
     RECT  26.136 34.476 26.304 34.512 ;
     RECT  26.328 34.476 26.496 34.512 ;
     RECT  26.52 34.476 26.688 34.512 ;
     RECT  26.712 34.476 26.88 34.512 ;
     RECT  26.904 34.476 27.072 34.512 ;
     RECT  27.096 34.476 27.264 34.512 ;
     RECT  27.288 34.476 27.456 34.512 ;
     RECT  27.48 34.476 27.648 34.512 ;
     RECT  27.672 34.476 27.84 34.512 ;
     RECT  27.864 34.476 28.032 34.512 ;
     RECT  28.056 34.476 28.224 34.512 ;
     RECT  28.248 34.476 28.416 34.512 ;
     RECT  28.44 34.476 28.608 34.512 ;
     RECT  28.632 34.476 28.8 34.512 ;
     RECT  28.824 34.476 28.992 34.512 ;
     RECT  29.016 34.476 29.184 34.512 ;
     RECT  8.664 0.563 9.792 1.763 ;
     RECT  26.52 0.563 27.84 1.763 ;
     RECT  29.064 0.611 29.208 2.137 ;
     RECT  8.664 1.763 10.176 2.915 ;
     RECT  16.536 1.763 17.664 3.443 ;
     RECT  26.52 1.763 28.416 1.811 ;
     RECT  26.52 1.811 27.012 2.137 ;
     RECT  26.82 2.137 27.012 2.151 ;
     RECT  8.28 2.915 8.424 3.877 ;
     RECT  11.4 3.443 12.576 4.501 ;
     RECT  16.392 3.443 17.664 3.875 ;
     RECT  28.608 3.443 28.704 4.549 ;
     RECT  16.212 3.875 17.664 5.029 ;
     RECT  11.4 5.123 12.576 5.171 ;
     RECT  11.4 5.171 12.672 5.219 ;
     RECT  11.4 5.219 12.72 6.899 ;
     RECT  16.212 5.267 17.664 5.747 ;
     RECT  16.212 5.747 16.344 7.189 ;
     RECT  22.632 5.795 24 5.891 ;
     RECT  23.904 5.891 24 6.757 ;
     RECT  24.552 6.229 25.536 6.757 ;
     RECT  14.232 6.323 15.264 13.187 ;
     RECT  11.208 6.899 12.72 16.357 ;
     RECT  25.08 8.003 26.4 17.699 ;
     RECT  16.968 8.629 18.336 9.059 ;
     RECT  8.424 9.109 9.744 9.587 ;
     RECT  8.424 9.587 8.52 9.589 ;
     RECT  2.712 10.741 3.888 11.939 ;
     RECT  3.912 10.741 5.1 11.939 ;
     RECT  4.608 11.939 5.1 13.045 ;
     RECT  22.104 11.941 23.616 12.563 ;
     RECT  5.592 13.139 5.88 14.197 ;
     RECT  14.232 13.187 15.456 16.595 ;
     RECT  2.712 14.149 3.936 14.197 ;
     RECT  5.928 14.485 7.104 14.867 ;
     RECT  5.688 14.867 7.104 16.595 ;
     RECT  8.52 15.301 9.888 16.355 ;
     RECT  28.608 16.019 28.8 17.317 ;
     RECT  10.272 16.355 10.5 17.317 ;
     RECT  11.496 16.357 12.72 16.979 ;
     RECT  5.592 16.595 7.104 16.643 ;
     RECT  15.408 16.595 15.456 17.605 ;
     RECT  11.496 16.979 12.816 17.699 ;
     RECT  18.912 17.171 19.176 17.221 ;
     RECT  18.912 17.221 20.208 17.459 ;
     RECT  28.608 17.317 28.704 17.461 ;
     RECT  25.032 17.699 26.4 18.563 ;
     RECT  24.312 18.563 26.4 18.709 ;
     RECT  24.312 18.709 25.776 19.379 ;
     RECT  18.384 18.851 18.6 18.997 ;
     RECT  21.168 18.851 21.3 19.909 ;
     RECT  16.212 18.997 17.232 19.093 ;
     RECT  17.256 18.997 18.6 19.331 ;
     RECT  2.712 19.283 3.744 20.003 ;
     RECT  17.16 19.331 18.6 19.861 ;
     RECT  17.16 19.861 18.48 21.011 ;
     RECT  2.712 20.003 3.936 20.195 ;
     RECT  19.656 20.485 21.168 21.731 ;
     RECT  17.16 21.011 18.6 21.637 ;
     RECT  17.352 21.637 18.6 23.893 ;
     RECT  16.488 23.987 17.616 29.363 ;
     RECT  8.808 25.045 9.84 29.219 ;
     RECT  27.144 29.029 28.608 29.123 ;
     RECT  27.144 29.123 28.656 29.605 ;
     RECT  7.392 29.363 7.8 30.757 ;
     RECT  16.488 29.363 17.904 29.459 ;
     RECT  11.784 29.605 13.2 31.909 ;
     RECT  21.612 29.605 23.04 31.909 ;
     RECT  27.384 29.605 28.656 30.851 ;
     RECT  5.412 30.757 6.864 30.899 ;
     RECT  16.212 30.803 16.488 31.909 ;
     RECT  8.112 30.851 8.808 31.621 ;
     RECT  27.384 30.851 29.4 32.053 ;
     RECT  5.412 30.899 7.8 31.909 ;
     RECT  8.112 31.621 10.32 31.909 ;
     RECT  8.112 31.909 9.216 32.389 ;
     RECT  9.24 31.909 10.32 32.389 ;
     RECT  11.784 31.909 13.056 32.389 ;
     RECT  19.608 31.909 21.12 32.437 ;
     RECT  25.176 31.909 26.7 32.389 ;
     RECT  27.672 32.053 29.4 32.197 ;
     RECT  27.672 32.197 29.184 32.389 ;
     RECT  17.496 32.389 18.6 32.437 ;
  END
END ot_hgi_coll_vmasm_slice16
END LIBRARY
